VERSION 5.7 ;
BUSBITCHARS "[]" ;
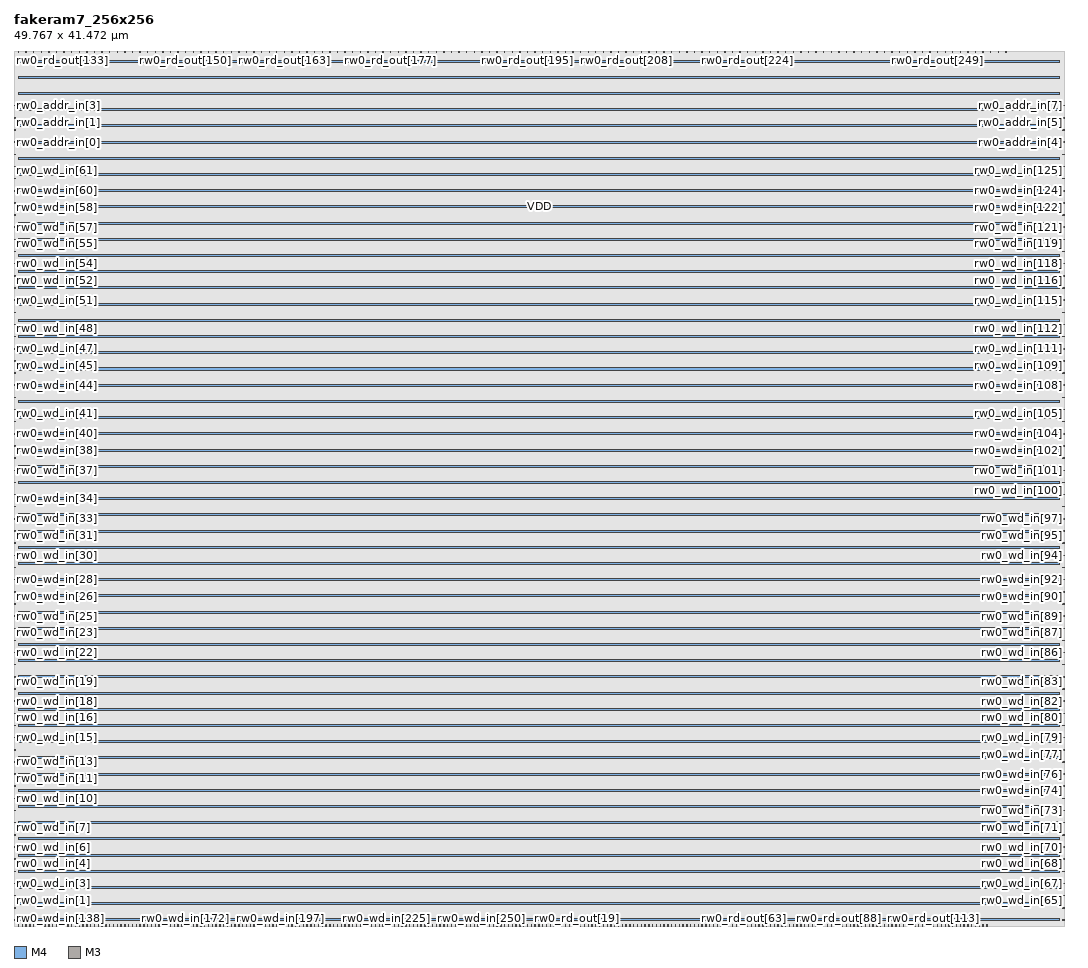
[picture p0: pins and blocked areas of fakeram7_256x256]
MACRO fakeram7_256x256
  FOREIGN fakeram7_256x256 0 0 ;
  SYMMETRY X Y R90 ;
  SIZE 49.767 BY 41.472 ;
  CLASS BLOCK ;
  PIN rw0_wd_in[0]
    DIRECTION INPUT ;
    USE SIGNAL ;
    SHAPE ABUTMENT ;
    PORT
      LAYER M4 ;
      RECT 0.000 0.276 0.072 0.300 ;
    END
  END rw0_wd_in[0]
  PIN rw0_wd_in[1]
    DIRECTION INPUT ;
    USE SIGNAL ;
    SHAPE ABUTMENT ;
    PORT
      LAYER M4 ;
      RECT 0.000 0.852 0.072 0.876 ;
    END
  END rw0_wd_in[1]
  PIN rw0_wd_in[2]
    DIRECTION INPUT ;
    USE SIGNAL ;
    SHAPE ABUTMENT ;
    PORT
      LAYER M4 ;
      RECT 0.000 1.428 0.072 1.452 ;
    END
  END rw0_wd_in[2]
  PIN rw0_wd_in[3]
    DIRECTION INPUT ;
    USE SIGNAL ;
    SHAPE ABUTMENT ;
    PORT
      LAYER M4 ;
      RECT 0.000 2.004 0.072 2.028 ;
    END
  END rw0_wd_in[3]
  PIN rw0_wd_in[4]
    DIRECTION INPUT ;
    USE SIGNAL ;
    SHAPE ABUTMENT ;
    PORT
      LAYER M4 ;
      RECT 0.000 2.580 0.072 2.604 ;
    END
  END rw0_wd_in[4]
  PIN rw0_wd_in[5]
    DIRECTION INPUT ;
    USE SIGNAL ;
    SHAPE ABUTMENT ;
    PORT
      LAYER M4 ;
      RECT 0.000 3.156 0.072 3.180 ;
    END
  END rw0_wd_in[5]
  PIN rw0_wd_in[6]
    DIRECTION INPUT ;
    USE SIGNAL ;
    SHAPE ABUTMENT ;
    PORT
      LAYER M4 ;
      RECT 0.000 3.732 0.072 3.756 ;
    END
  END rw0_wd_in[6]
  PIN rw0_wd_in[7]
    DIRECTION INPUT ;
    USE SIGNAL ;
    SHAPE ABUTMENT ;
    PORT
      LAYER M4 ;
      RECT 0.000 4.308 0.072 4.332 ;
    END
  END rw0_wd_in[7]
  PIN rw0_wd_in[8]
    DIRECTION INPUT ;
    USE SIGNAL ;
    SHAPE ABUTMENT ;
    PORT
      LAYER M4 ;
      RECT 0.000 4.884 0.072 4.908 ;
    END
  END rw0_wd_in[8]
  PIN rw0_wd_in[9]
    DIRECTION INPUT ;
    USE SIGNAL ;
    SHAPE ABUTMENT ;
    PORT
      LAYER M4 ;
      RECT 0.000 5.460 0.072 5.484 ;
    END
  END rw0_wd_in[9]
  PIN rw0_wd_in[10]
    DIRECTION INPUT ;
    USE SIGNAL ;
    SHAPE ABUTMENT ;
    PORT
      LAYER M4 ;
      RECT 0.000 6.036 0.072 6.060 ;
    END
  END rw0_wd_in[10]
  PIN rw0_wd_in[11]
    DIRECTION INPUT ;
    USE SIGNAL ;
    SHAPE ABUTMENT ;
    PORT
      LAYER M4 ;
      RECT 0.000 6.612 0.072 6.636 ;
    END
  END rw0_wd_in[11]
  PIN rw0_wd_in[12]
    DIRECTION INPUT ;
    USE SIGNAL ;
    SHAPE ABUTMENT ;
    PORT
      LAYER M4 ;
      RECT 0.000 7.188 0.072 7.212 ;
    END
  END rw0_wd_in[12]
  PIN rw0_wd_in[13]
    DIRECTION INPUT ;
    USE SIGNAL ;
    SHAPE ABUTMENT ;
    PORT
      LAYER M4 ;
      RECT 0.000 7.764 0.072 7.788 ;
    END
  END rw0_wd_in[13]
  PIN rw0_wd_in[14]
    DIRECTION INPUT ;
    USE SIGNAL ;
    SHAPE ABUTMENT ;
    PORT
      LAYER M4 ;
      RECT 0.000 8.340 0.072 8.364 ;
    END
  END rw0_wd_in[14]
  PIN rw0_wd_in[15]
    DIRECTION INPUT ;
    USE SIGNAL ;
    SHAPE ABUTMENT ;
    PORT
      LAYER M4 ;
      RECT 0.000 8.916 0.072 8.940 ;
    END
  END rw0_wd_in[15]
  PIN rw0_wd_in[16]
    DIRECTION INPUT ;
    USE SIGNAL ;
    SHAPE ABUTMENT ;
    PORT
      LAYER M4 ;
      RECT 0.000 9.492 0.072 9.516 ;
    END
  END rw0_wd_in[16]
  PIN rw0_wd_in[17]
    DIRECTION INPUT ;
    USE SIGNAL ;
    SHAPE ABUTMENT ;
    PORT
      LAYER M4 ;
      RECT 0.000 10.068 0.072 10.092 ;
    END
  END rw0_wd_in[17]
  PIN rw0_wd_in[18]
    DIRECTION INPUT ;
    USE SIGNAL ;
    SHAPE ABUTMENT ;
    PORT
      LAYER M4 ;
      RECT 0.000 10.644 0.072 10.668 ;
    END
  END rw0_wd_in[18]
  PIN rw0_wd_in[19]
    DIRECTION INPUT ;
    USE SIGNAL ;
    SHAPE ABUTMENT ;
    PORT
      LAYER M4 ;
      RECT 0.000 11.220 0.072 11.244 ;
    END
  END rw0_wd_in[19]
  PIN rw0_wd_in[20]
    DIRECTION INPUT ;
    USE SIGNAL ;
    SHAPE ABUTMENT ;
    PORT
      LAYER M4 ;
      RECT 0.000 11.796 0.072 11.820 ;
    END
  END rw0_wd_in[20]
  PIN rw0_wd_in[21]
    DIRECTION INPUT ;
    USE SIGNAL ;
    SHAPE ABUTMENT ;
    PORT
      LAYER M4 ;
      RECT 0.000 12.372 0.072 12.396 ;
    END
  END rw0_wd_in[21]
  PIN rw0_wd_in[22]
    DIRECTION INPUT ;
    USE SIGNAL ;
    SHAPE ABUTMENT ;
    PORT
      LAYER M4 ;
      RECT 0.000 12.948 0.072 12.972 ;
    END
  END rw0_wd_in[22]
  PIN rw0_wd_in[23]
    DIRECTION INPUT ;
    USE SIGNAL ;
    SHAPE ABUTMENT ;
    PORT
      LAYER M4 ;
      RECT 0.000 13.524 0.072 13.548 ;
    END
  END rw0_wd_in[23]
  PIN rw0_wd_in[24]
    DIRECTION INPUT ;
    USE SIGNAL ;
    SHAPE ABUTMENT ;
    PORT
      LAYER M4 ;
      RECT 0.000 14.100 0.072 14.124 ;
    END
  END rw0_wd_in[24]
  PIN rw0_wd_in[25]
    DIRECTION INPUT ;
    USE SIGNAL ;
    SHAPE ABUTMENT ;
    PORT
      LAYER M4 ;
      RECT 0.000 14.676 0.072 14.700 ;
    END
  END rw0_wd_in[25]
  PIN rw0_wd_in[26]
    DIRECTION INPUT ;
    USE SIGNAL ;
    SHAPE ABUTMENT ;
    PORT
      LAYER M4 ;
      RECT 0.000 15.252 0.072 15.276 ;
    END
  END rw0_wd_in[26]
  PIN rw0_wd_in[27]
    DIRECTION INPUT ;
    USE SIGNAL ;
    SHAPE ABUTMENT ;
    PORT
      LAYER M4 ;
      RECT 0.000 15.828 0.072 15.852 ;
    END
  END rw0_wd_in[27]
  PIN rw0_wd_in[28]
    DIRECTION INPUT ;
    USE SIGNAL ;
    SHAPE ABUTMENT ;
    PORT
      LAYER M4 ;
      RECT 0.000 16.404 0.072 16.428 ;
    END
  END rw0_wd_in[28]
  PIN rw0_wd_in[29]
    DIRECTION INPUT ;
    USE SIGNAL ;
    SHAPE ABUTMENT ;
    PORT
      LAYER M4 ;
      RECT 0.000 16.980 0.072 17.004 ;
    END
  END rw0_wd_in[29]
  PIN rw0_wd_in[30]
    DIRECTION INPUT ;
    USE SIGNAL ;
    SHAPE ABUTMENT ;
    PORT
      LAYER M4 ;
      RECT 0.000 17.556 0.072 17.580 ;
    END
  END rw0_wd_in[30]
  PIN rw0_wd_in[31]
    DIRECTION INPUT ;
    USE SIGNAL ;
    SHAPE ABUTMENT ;
    PORT
      LAYER M4 ;
      RECT 0.000 18.132 0.072 18.156 ;
    END
  END rw0_wd_in[31]
  PIN rw0_wd_in[32]
    DIRECTION INPUT ;
    USE SIGNAL ;
    SHAPE ABUTMENT ;
    PORT
      LAYER M4 ;
      RECT 0.000 18.708 0.072 18.732 ;
    END
  END rw0_wd_in[32]
  PIN rw0_wd_in[33]
    DIRECTION INPUT ;
    USE SIGNAL ;
    SHAPE ABUTMENT ;
    PORT
      LAYER M4 ;
      RECT 0.000 19.284 0.072 19.308 ;
    END
  END rw0_wd_in[33]
  PIN rw0_wd_in[34]
    DIRECTION INPUT ;
    USE SIGNAL ;
    SHAPE ABUTMENT ;
    PORT
      LAYER M4 ;
      RECT 0.000 19.860 0.072 19.884 ;
    END
  END rw0_wd_in[34]
  PIN rw0_wd_in[35]
    DIRECTION INPUT ;
    USE SIGNAL ;
    SHAPE ABUTMENT ;
    PORT
      LAYER M4 ;
      RECT 0.000 20.436 0.072 20.460 ;
    END
  END rw0_wd_in[35]
  PIN rw0_wd_in[36]
    DIRECTION INPUT ;
    USE SIGNAL ;
    SHAPE ABUTMENT ;
    PORT
      LAYER M4 ;
      RECT 0.000 21.012 0.072 21.036 ;
    END
  END rw0_wd_in[36]
  PIN rw0_wd_in[37]
    DIRECTION INPUT ;
    USE SIGNAL ;
    SHAPE ABUTMENT ;
    PORT
      LAYER M4 ;
      RECT 0.000 21.588 0.072 21.612 ;
    END
  END rw0_wd_in[37]
  PIN rw0_wd_in[38]
    DIRECTION INPUT ;
    USE SIGNAL ;
    SHAPE ABUTMENT ;
    PORT
      LAYER M4 ;
      RECT 0.000 22.164 0.072 22.188 ;
    END
  END rw0_wd_in[38]
  PIN rw0_wd_in[39]
    DIRECTION INPUT ;
    USE SIGNAL ;
    SHAPE ABUTMENT ;
    PORT
      LAYER M4 ;
      RECT 0.000 22.740 0.072 22.764 ;
    END
  END rw0_wd_in[39]
  PIN rw0_wd_in[40]
    DIRECTION INPUT ;
    USE SIGNAL ;
    SHAPE ABUTMENT ;
    PORT
      LAYER M4 ;
      RECT 0.000 23.316 0.072 23.340 ;
    END
  END rw0_wd_in[40]
  PIN rw0_wd_in[41]
    DIRECTION INPUT ;
    USE SIGNAL ;
    SHAPE ABUTMENT ;
    PORT
      LAYER M4 ;
      RECT 0.000 23.892 0.072 23.916 ;
    END
  END rw0_wd_in[41]
  PIN rw0_wd_in[42]
    DIRECTION INPUT ;
    USE SIGNAL ;
    SHAPE ABUTMENT ;
    PORT
      LAYER M4 ;
      RECT 0.000 24.468 0.072 24.492 ;
    END
  END rw0_wd_in[42]
  PIN rw0_wd_in[43]
    DIRECTION INPUT ;
    USE SIGNAL ;
    SHAPE ABUTMENT ;
    PORT
      LAYER M4 ;
      RECT 0.000 25.044 0.072 25.068 ;
    END
  END rw0_wd_in[43]
  PIN rw0_wd_in[44]
    DIRECTION INPUT ;
    USE SIGNAL ;
    SHAPE ABUTMENT ;
    PORT
      LAYER M4 ;
      RECT 0.000 25.620 0.072 25.644 ;
    END
  END rw0_wd_in[44]
  PIN rw0_wd_in[45]
    DIRECTION INPUT ;
    USE SIGNAL ;
    SHAPE ABUTMENT ;
    PORT
      LAYER M4 ;
      RECT 0.000 26.196 0.072 26.220 ;
    END
  END rw0_wd_in[45]
  PIN rw0_wd_in[46]
    DIRECTION INPUT ;
    USE SIGNAL ;
    SHAPE ABUTMENT ;
    PORT
      LAYER M4 ;
      RECT 0.000 26.772 0.072 26.796 ;
    END
  END rw0_wd_in[46]
  PIN rw0_wd_in[47]
    DIRECTION INPUT ;
    USE SIGNAL ;
    SHAPE ABUTMENT ;
    PORT
      LAYER M4 ;
      RECT 0.000 27.348 0.072 27.372 ;
    END
  END rw0_wd_in[47]
  PIN rw0_wd_in[48]
    DIRECTION INPUT ;
    USE SIGNAL ;
    SHAPE ABUTMENT ;
    PORT
      LAYER M4 ;
      RECT 0.000 27.924 0.072 27.948 ;
    END
  END rw0_wd_in[48]
  PIN rw0_wd_in[49]
    DIRECTION INPUT ;
    USE SIGNAL ;
    SHAPE ABUTMENT ;
    PORT
      LAYER M4 ;
      RECT 0.000 28.500 0.072 28.524 ;
    END
  END rw0_wd_in[49]
  PIN rw0_wd_in[50]
    DIRECTION INPUT ;
    USE SIGNAL ;
    SHAPE ABUTMENT ;
    PORT
      LAYER M4 ;
      RECT 0.000 29.076 0.072 29.100 ;
    END
  END rw0_wd_in[50]
  PIN rw0_wd_in[51]
    DIRECTION INPUT ;
    USE SIGNAL ;
    SHAPE ABUTMENT ;
    PORT
      LAYER M4 ;
      RECT 0.000 29.652 0.072 29.676 ;
    END
  END rw0_wd_in[51]
  PIN rw0_wd_in[52]
    DIRECTION INPUT ;
    USE SIGNAL ;
    SHAPE ABUTMENT ;
    PORT
      LAYER M4 ;
      RECT 0.000 30.228 0.072 30.252 ;
    END
  END rw0_wd_in[52]
  PIN rw0_wd_in[53]
    DIRECTION INPUT ;
    USE SIGNAL ;
    SHAPE ABUTMENT ;
    PORT
      LAYER M4 ;
      RECT 0.000 30.804 0.072 30.828 ;
    END
  END rw0_wd_in[53]
  PIN rw0_wd_in[54]
    DIRECTION INPUT ;
    USE SIGNAL ;
    SHAPE ABUTMENT ;
    PORT
      LAYER M4 ;
      RECT 0.000 31.380 0.072 31.404 ;
    END
  END rw0_wd_in[54]
  PIN rw0_wd_in[55]
    DIRECTION INPUT ;
    USE SIGNAL ;
    SHAPE ABUTMENT ;
    PORT
      LAYER M4 ;
      RECT 0.000 31.956 0.072 31.980 ;
    END
  END rw0_wd_in[55]
  PIN rw0_wd_in[56]
    DIRECTION INPUT ;
    USE SIGNAL ;
    SHAPE ABUTMENT ;
    PORT
      LAYER M4 ;
      RECT 0.000 32.532 0.072 32.556 ;
    END
  END rw0_wd_in[56]
  PIN rw0_wd_in[57]
    DIRECTION INPUT ;
    USE SIGNAL ;
    SHAPE ABUTMENT ;
    PORT
      LAYER M4 ;
      RECT 0.000 33.108 0.072 33.132 ;
    END
  END rw0_wd_in[57]
  PIN rw0_wd_in[58]
    DIRECTION INPUT ;
    USE SIGNAL ;
    SHAPE ABUTMENT ;
    PORT
      LAYER M4 ;
      RECT 0.000 33.684 0.072 33.708 ;
    END
  END rw0_wd_in[58]
  PIN rw0_wd_in[59]
    DIRECTION INPUT ;
    USE SIGNAL ;
    SHAPE ABUTMENT ;
    PORT
      LAYER M4 ;
      RECT 0.000 34.260 0.072 34.284 ;
    END
  END rw0_wd_in[59]
  PIN rw0_wd_in[60]
    DIRECTION INPUT ;
    USE SIGNAL ;
    SHAPE ABUTMENT ;
    PORT
      LAYER M4 ;
      RECT 0.000 34.836 0.072 34.860 ;
    END
  END rw0_wd_in[60]
  PIN rw0_wd_in[61]
    DIRECTION INPUT ;
    USE SIGNAL ;
    SHAPE ABUTMENT ;
    PORT
      LAYER M4 ;
      RECT 0.000 35.412 0.072 35.436 ;
    END
  END rw0_wd_in[61]
  PIN rw0_wd_in[62]
    DIRECTION INPUT ;
    USE SIGNAL ;
    SHAPE ABUTMENT ;
    PORT
      LAYER M4 ;
      RECT 0.000 35.988 0.072 36.012 ;
    END
  END rw0_wd_in[62]
  PIN rw0_wd_in[63]
    DIRECTION INPUT ;
    USE SIGNAL ;
    SHAPE ABUTMENT ;
    PORT
      LAYER M4 ;
      RECT 0.000 36.564 0.072 36.588 ;
    END
  END rw0_wd_in[63]
  PIN rw0_wd_in[64]
    DIRECTION INPUT ;
    USE SIGNAL ;
    SHAPE ABUTMENT ;
    PORT
      LAYER M4 ;
      RECT 49.695 0.276 49.767 0.300 ;
    END
  END rw0_wd_in[64]
  PIN rw0_wd_in[65]
    DIRECTION INPUT ;
    USE SIGNAL ;
    SHAPE ABUTMENT ;
    PORT
      LAYER M4 ;
      RECT 49.695 0.852 49.767 0.876 ;
    END
  END rw0_wd_in[65]
  PIN rw0_wd_in[66]
    DIRECTION INPUT ;
    USE SIGNAL ;
    SHAPE ABUTMENT ;
    PORT
      LAYER M4 ;
      RECT 49.695 1.428 49.767 1.452 ;
    END
  END rw0_wd_in[66]
  PIN rw0_wd_in[67]
    DIRECTION INPUT ;
    USE SIGNAL ;
    SHAPE ABUTMENT ;
    PORT
      LAYER M4 ;
      RECT 49.695 2.004 49.767 2.028 ;
    END
  END rw0_wd_in[67]
  PIN rw0_wd_in[68]
    DIRECTION INPUT ;
    USE SIGNAL ;
    SHAPE ABUTMENT ;
    PORT
      LAYER M4 ;
      RECT 49.695 2.580 49.767 2.604 ;
    END
  END rw0_wd_in[68]
  PIN rw0_wd_in[69]
    DIRECTION INPUT ;
    USE SIGNAL ;
    SHAPE ABUTMENT ;
    PORT
      LAYER M4 ;
      RECT 49.695 3.156 49.767 3.180 ;
    END
  END rw0_wd_in[69]
  PIN rw0_wd_in[70]
    DIRECTION INPUT ;
    USE SIGNAL ;
    SHAPE ABUTMENT ;
    PORT
      LAYER M4 ;
      RECT 49.695 3.732 49.767 3.756 ;
    END
  END rw0_wd_in[70]
  PIN rw0_wd_in[71]
    DIRECTION INPUT ;
    USE SIGNAL ;
    SHAPE ABUTMENT ;
    PORT
      LAYER M4 ;
      RECT 49.695 4.308 49.767 4.332 ;
    END
  END rw0_wd_in[71]
  PIN rw0_wd_in[72]
    DIRECTION INPUT ;
    USE SIGNAL ;
    SHAPE ABUTMENT ;
    PORT
      LAYER M4 ;
      RECT 49.695 4.884 49.767 4.908 ;
    END
  END rw0_wd_in[72]
  PIN rw0_wd_in[73]
    DIRECTION INPUT ;
    USE SIGNAL ;
    SHAPE ABUTMENT ;
    PORT
      LAYER M4 ;
      RECT 49.695 5.460 49.767 5.484 ;
    END
  END rw0_wd_in[73]
  PIN rw0_wd_in[74]
    DIRECTION INPUT ;
    USE SIGNAL ;
    SHAPE ABUTMENT ;
    PORT
      LAYER M4 ;
      RECT 49.695 6.036 49.767 6.060 ;
    END
  END rw0_wd_in[74]
  PIN rw0_wd_in[75]
    DIRECTION INPUT ;
    USE SIGNAL ;
    SHAPE ABUTMENT ;
    PORT
      LAYER M4 ;
      RECT 49.695 6.612 49.767 6.636 ;
    END
  END rw0_wd_in[75]
  PIN rw0_wd_in[76]
    DIRECTION INPUT ;
    USE SIGNAL ;
    SHAPE ABUTMENT ;
    PORT
      LAYER M4 ;
      RECT 49.695 7.188 49.767 7.212 ;
    END
  END rw0_wd_in[76]
  PIN rw0_wd_in[77]
    DIRECTION INPUT ;
    USE SIGNAL ;
    SHAPE ABUTMENT ;
    PORT
      LAYER M4 ;
      RECT 49.695 7.764 49.767 7.788 ;
    END
  END rw0_wd_in[77]
  PIN rw0_wd_in[78]
    DIRECTION INPUT ;
    USE SIGNAL ;
    SHAPE ABUTMENT ;
    PORT
      LAYER M4 ;
      RECT 49.695 8.340 49.767 8.364 ;
    END
  END rw0_wd_in[78]
  PIN rw0_wd_in[79]
    DIRECTION INPUT ;
    USE SIGNAL ;
    SHAPE ABUTMENT ;
    PORT
      LAYER M4 ;
      RECT 49.695 8.916 49.767 8.940 ;
    END
  END rw0_wd_in[79]
  PIN rw0_wd_in[80]
    DIRECTION INPUT ;
    USE SIGNAL ;
    SHAPE ABUTMENT ;
    PORT
      LAYER M4 ;
      RECT 49.695 9.492 49.767 9.516 ;
    END
  END rw0_wd_in[80]
  PIN rw0_wd_in[81]
    DIRECTION INPUT ;
    USE SIGNAL ;
    SHAPE ABUTMENT ;
    PORT
      LAYER M4 ;
      RECT 49.695 10.068 49.767 10.092 ;
    END
  END rw0_wd_in[81]
  PIN rw0_wd_in[82]
    DIRECTION INPUT ;
    USE SIGNAL ;
    SHAPE ABUTMENT ;
    PORT
      LAYER M4 ;
      RECT 49.695 10.644 49.767 10.668 ;
    END
  END rw0_wd_in[82]
  PIN rw0_wd_in[83]
    DIRECTION INPUT ;
    USE SIGNAL ;
    SHAPE ABUTMENT ;
    PORT
      LAYER M4 ;
      RECT 49.695 11.220 49.767 11.244 ;
    END
  END rw0_wd_in[83]
  PIN rw0_wd_in[84]
    DIRECTION INPUT ;
    USE SIGNAL ;
    SHAPE ABUTMENT ;
    PORT
      LAYER M4 ;
      RECT 49.695 11.796 49.767 11.820 ;
    END
  END rw0_wd_in[84]
  PIN rw0_wd_in[85]
    DIRECTION INPUT ;
    USE SIGNAL ;
    SHAPE ABUTMENT ;
    PORT
      LAYER M4 ;
      RECT 49.695 12.372 49.767 12.396 ;
    END
  END rw0_wd_in[85]
  PIN rw0_wd_in[86]
    DIRECTION INPUT ;
    USE SIGNAL ;
    SHAPE ABUTMENT ;
    PORT
      LAYER M4 ;
      RECT 49.695 12.948 49.767 12.972 ;
    END
  END rw0_wd_in[86]
  PIN rw0_wd_in[87]
    DIRECTION INPUT ;
    USE SIGNAL ;
    SHAPE ABUTMENT ;
    PORT
      LAYER M4 ;
      RECT 49.695 13.524 49.767 13.548 ;
    END
  END rw0_wd_in[87]
  PIN rw0_wd_in[88]
    DIRECTION INPUT ;
    USE SIGNAL ;
    SHAPE ABUTMENT ;
    PORT
      LAYER M4 ;
      RECT 49.695 14.100 49.767 14.124 ;
    END
  END rw0_wd_in[88]
  PIN rw0_wd_in[89]
    DIRECTION INPUT ;
    USE SIGNAL ;
    SHAPE ABUTMENT ;
    PORT
      LAYER M4 ;
      RECT 49.695 14.676 49.767 14.700 ;
    END
  END rw0_wd_in[89]
  PIN rw0_wd_in[90]
    DIRECTION INPUT ;
    USE SIGNAL ;
    SHAPE ABUTMENT ;
    PORT
      LAYER M4 ;
      RECT 49.695 15.252 49.767 15.276 ;
    END
  END rw0_wd_in[90]
  PIN rw0_wd_in[91]
    DIRECTION INPUT ;
    USE SIGNAL ;
    SHAPE ABUTMENT ;
    PORT
      LAYER M4 ;
      RECT 49.695 15.828 49.767 15.852 ;
    END
  END rw0_wd_in[91]
  PIN rw0_wd_in[92]
    DIRECTION INPUT ;
    USE SIGNAL ;
    SHAPE ABUTMENT ;
    PORT
      LAYER M4 ;
      RECT 49.695 16.404 49.767 16.428 ;
    END
  END rw0_wd_in[92]
  PIN rw0_wd_in[93]
    DIRECTION INPUT ;
    USE SIGNAL ;
    SHAPE ABUTMENT ;
    PORT
      LAYER M4 ;
      RECT 49.695 16.980 49.767 17.004 ;
    END
  END rw0_wd_in[93]
  PIN rw0_wd_in[94]
    DIRECTION INPUT ;
    USE SIGNAL ;
    SHAPE ABUTMENT ;
    PORT
      LAYER M4 ;
      RECT 49.695 17.556 49.767 17.580 ;
    END
  END rw0_wd_in[94]
  PIN rw0_wd_in[95]
    DIRECTION INPUT ;
    USE SIGNAL ;
    SHAPE ABUTMENT ;
    PORT
      LAYER M4 ;
      RECT 49.695 18.132 49.767 18.156 ;
    END
  END rw0_wd_in[95]
  PIN rw0_wd_in[96]
    DIRECTION INPUT ;
    USE SIGNAL ;
    SHAPE ABUTMENT ;
    PORT
      LAYER M4 ;
      RECT 49.695 18.708 49.767 18.732 ;
    END
  END rw0_wd_in[96]
  PIN rw0_wd_in[97]
    DIRECTION INPUT ;
    USE SIGNAL ;
    SHAPE ABUTMENT ;
    PORT
      LAYER M4 ;
      RECT 49.695 19.284 49.767 19.308 ;
    END
  END rw0_wd_in[97]
  PIN rw0_wd_in[98]
    DIRECTION INPUT ;
    USE SIGNAL ;
    SHAPE ABUTMENT ;
    PORT
      LAYER M4 ;
      RECT 49.695 19.860 49.767 19.884 ;
    END
  END rw0_wd_in[98]
  PIN rw0_wd_in[99]
    DIRECTION INPUT ;
    USE SIGNAL ;
    SHAPE ABUTMENT ;
    PORT
      LAYER M4 ;
      RECT 49.695 20.436 49.767 20.460 ;
    END
  END rw0_wd_in[99]
  PIN rw0_wd_in[100]
    DIRECTION INPUT ;
    USE SIGNAL ;
    SHAPE ABUTMENT ;
    PORT
      LAYER M4 ;
      RECT 49.695 21.012 49.767 21.036 ;
    END
  END rw0_wd_in[100]
  PIN rw0_wd_in[101]
    DIRECTION INPUT ;
    USE SIGNAL ;
    SHAPE ABUTMENT ;
    PORT
      LAYER M4 ;
      RECT 49.695 21.588 49.767 21.612 ;
    END
  END rw0_wd_in[101]
  PIN rw0_wd_in[102]
    DIRECTION INPUT ;
    USE SIGNAL ;
    SHAPE ABUTMENT ;
    PORT
      LAYER M4 ;
      RECT 49.695 22.164 49.767 22.188 ;
    END
  END rw0_wd_in[102]
  PIN rw0_wd_in[103]
    DIRECTION INPUT ;
    USE SIGNAL ;
    SHAPE ABUTMENT ;
    PORT
      LAYER M4 ;
      RECT 49.695 22.740 49.767 22.764 ;
    END
  END rw0_wd_in[103]
  PIN rw0_wd_in[104]
    DIRECTION INPUT ;
    USE SIGNAL ;
    SHAPE ABUTMENT ;
    PORT
      LAYER M4 ;
      RECT 49.695 23.316 49.767 23.340 ;
    END
  END rw0_wd_in[104]
  PIN rw0_wd_in[105]
    DIRECTION INPUT ;
    USE SIGNAL ;
    SHAPE ABUTMENT ;
    PORT
      LAYER M4 ;
      RECT 49.695 23.892 49.767 23.916 ;
    END
  END rw0_wd_in[105]
  PIN rw0_wd_in[106]
    DIRECTION INPUT ;
    USE SIGNAL ;
    SHAPE ABUTMENT ;
    PORT
      LAYER M4 ;
      RECT 49.695 24.468 49.767 24.492 ;
    END
  END rw0_wd_in[106]
  PIN rw0_wd_in[107]
    DIRECTION INPUT ;
    USE SIGNAL ;
    SHAPE ABUTMENT ;
    PORT
      LAYER M4 ;
      RECT 49.695 25.044 49.767 25.068 ;
    END
  END rw0_wd_in[107]
  PIN rw0_wd_in[108]
    DIRECTION INPUT ;
    USE SIGNAL ;
    SHAPE ABUTMENT ;
    PORT
      LAYER M4 ;
      RECT 49.695 25.620 49.767 25.644 ;
    END
  END rw0_wd_in[108]
  PIN rw0_wd_in[109]
    DIRECTION INPUT ;
    USE SIGNAL ;
    SHAPE ABUTMENT ;
    PORT
      LAYER M4 ;
      RECT 49.695 26.196 49.767 26.220 ;
    END
  END rw0_wd_in[109]
  PIN rw0_wd_in[110]
    DIRECTION INPUT ;
    USE SIGNAL ;
    SHAPE ABUTMENT ;
    PORT
      LAYER M4 ;
      RECT 49.695 26.772 49.767 26.796 ;
    END
  END rw0_wd_in[110]
  PIN rw0_wd_in[111]
    DIRECTION INPUT ;
    USE SIGNAL ;
    SHAPE ABUTMENT ;
    PORT
      LAYER M4 ;
      RECT 49.695 27.348 49.767 27.372 ;
    END
  END rw0_wd_in[111]
  PIN rw0_wd_in[112]
    DIRECTION INPUT ;
    USE SIGNAL ;
    SHAPE ABUTMENT ;
    PORT
      LAYER M4 ;
      RECT 49.695 27.924 49.767 27.948 ;
    END
  END rw0_wd_in[112]
  PIN rw0_wd_in[113]
    DIRECTION INPUT ;
    USE SIGNAL ;
    SHAPE ABUTMENT ;
    PORT
      LAYER M4 ;
      RECT 49.695 28.500 49.767 28.524 ;
    END
  END rw0_wd_in[113]
  PIN rw0_wd_in[114]
    DIRECTION INPUT ;
    USE SIGNAL ;
    SHAPE ABUTMENT ;
    PORT
      LAYER M4 ;
      RECT 49.695 29.076 49.767 29.100 ;
    END
  END rw0_wd_in[114]
  PIN rw0_wd_in[115]
    DIRECTION INPUT ;
    USE SIGNAL ;
    SHAPE ABUTMENT ;
    PORT
      LAYER M4 ;
      RECT 49.695 29.652 49.767 29.676 ;
    END
  END rw0_wd_in[115]
  PIN rw0_wd_in[116]
    DIRECTION INPUT ;
    USE SIGNAL ;
    SHAPE ABUTMENT ;
    PORT
      LAYER M4 ;
      RECT 49.695 30.228 49.767 30.252 ;
    END
  END rw0_wd_in[116]
  PIN rw0_wd_in[117]
    DIRECTION INPUT ;
    USE SIGNAL ;
    SHAPE ABUTMENT ;
    PORT
      LAYER M4 ;
      RECT 49.695 30.804 49.767 30.828 ;
    END
  END rw0_wd_in[117]
  PIN rw0_wd_in[118]
    DIRECTION INPUT ;
    USE SIGNAL ;
    SHAPE ABUTMENT ;
    PORT
      LAYER M4 ;
      RECT 49.695 31.380 49.767 31.404 ;
    END
  END rw0_wd_in[118]
  PIN rw0_wd_in[119]
    DIRECTION INPUT ;
    USE SIGNAL ;
    SHAPE ABUTMENT ;
    PORT
      LAYER M4 ;
      RECT 49.695 31.956 49.767 31.980 ;
    END
  END rw0_wd_in[119]
  PIN rw0_wd_in[120]
    DIRECTION INPUT ;
    USE SIGNAL ;
    SHAPE ABUTMENT ;
    PORT
      LAYER M4 ;
      RECT 49.695 32.532 49.767 32.556 ;
    END
  END rw0_wd_in[120]
  PIN rw0_wd_in[121]
    DIRECTION INPUT ;
    USE SIGNAL ;
    SHAPE ABUTMENT ;
    PORT
      LAYER M4 ;
      RECT 49.695 33.108 49.767 33.132 ;
    END
  END rw0_wd_in[121]
  PIN rw0_wd_in[122]
    DIRECTION INPUT ;
    USE SIGNAL ;
    SHAPE ABUTMENT ;
    PORT
      LAYER M4 ;
      RECT 49.695 33.684 49.767 33.708 ;
    END
  END rw0_wd_in[122]
  PIN rw0_wd_in[123]
    DIRECTION INPUT ;
    USE SIGNAL ;
    SHAPE ABUTMENT ;
    PORT
      LAYER M4 ;
      RECT 49.695 34.260 49.767 34.284 ;
    END
  END rw0_wd_in[123]
  PIN rw0_wd_in[124]
    DIRECTION INPUT ;
    USE SIGNAL ;
    SHAPE ABUTMENT ;
    PORT
      LAYER M4 ;
      RECT 49.695 34.836 49.767 34.860 ;
    END
  END rw0_wd_in[124]
  PIN rw0_wd_in[125]
    DIRECTION INPUT ;
    USE SIGNAL ;
    SHAPE ABUTMENT ;
    PORT
      LAYER M4 ;
      RECT 49.695 35.412 49.767 35.436 ;
    END
  END rw0_wd_in[125]
  PIN rw0_wd_in[126]
    DIRECTION INPUT ;
    USE SIGNAL ;
    SHAPE ABUTMENT ;
    PORT
      LAYER M4 ;
      RECT 49.695 35.988 49.767 36.012 ;
    END
  END rw0_wd_in[126]
  PIN rw0_wd_in[127]
    DIRECTION INPUT ;
    USE SIGNAL ;
    SHAPE ABUTMENT ;
    PORT
      LAYER M4 ;
      RECT 49.695 36.564 49.767 36.588 ;
    END
  END rw0_wd_in[127]
  PIN rw0_wd_in[128]
    DIRECTION OUTPUT ;
    USE SIGNAL ;
    SHAPE ABUTMENT ;
    PORT
      LAYER M3 ;
      RECT 0.207 0.000 0.225 0.054 ;
    END
  END rw0_wd_in[128]
  PIN rw0_wd_in[129]
    DIRECTION OUTPUT ;
    USE SIGNAL ;
    SHAPE ABUTMENT ;
    PORT
      LAYER M3 ;
      RECT 0.387 0.000 0.405 0.054 ;
    END
  END rw0_wd_in[129]
  PIN rw0_wd_in[130]
    DIRECTION OUTPUT ;
    USE SIGNAL ;
    SHAPE ABUTMENT ;
    PORT
      LAYER M3 ;
      RECT 0.567 0.000 0.585 0.054 ;
    END
  END rw0_wd_in[130]
  PIN rw0_wd_in[131]
    DIRECTION OUTPUT ;
    USE SIGNAL ;
    SHAPE ABUTMENT ;
    PORT
      LAYER M3 ;
      RECT 0.747 0.000 0.765 0.054 ;
    END
  END rw0_wd_in[131]
  PIN rw0_wd_in[132]
    DIRECTION OUTPUT ;
    USE SIGNAL ;
    SHAPE ABUTMENT ;
    PORT
      LAYER M3 ;
      RECT 0.927 0.000 0.945 0.054 ;
    END
  END rw0_wd_in[132]
  PIN rw0_wd_in[133]
    DIRECTION OUTPUT ;
    USE SIGNAL ;
    SHAPE ABUTMENT ;
    PORT
      LAYER M3 ;
      RECT 1.107 0.000 1.125 0.054 ;
    END
  END rw0_wd_in[133]
  PIN rw0_wd_in[134]
    DIRECTION OUTPUT ;
    USE SIGNAL ;
    SHAPE ABUTMENT ;
    PORT
      LAYER M3 ;
      RECT 1.287 0.000 1.305 0.054 ;
    END
  END rw0_wd_in[134]
  PIN rw0_wd_in[135]
    DIRECTION OUTPUT ;
    USE SIGNAL ;
    SHAPE ABUTMENT ;
    PORT
      LAYER M3 ;
      RECT 1.467 0.000 1.485 0.054 ;
    END
  END rw0_wd_in[135]
  PIN rw0_wd_in[136]
    DIRECTION OUTPUT ;
    USE SIGNAL ;
    SHAPE ABUTMENT ;
    PORT
      LAYER M3 ;
      RECT 1.647 0.000 1.665 0.054 ;
    END
  END rw0_wd_in[136]
  PIN rw0_wd_in[137]
    DIRECTION OUTPUT ;
    USE SIGNAL ;
    SHAPE ABUTMENT ;
    PORT
      LAYER M3 ;
      RECT 1.827 0.000 1.845 0.054 ;
    END
  END rw0_wd_in[137]
  PIN rw0_wd_in[138]
    DIRECTION OUTPUT ;
    USE SIGNAL ;
    SHAPE ABUTMENT ;
    PORT
      LAYER M3 ;
      RECT 2.007 0.000 2.025 0.054 ;
    END
  END rw0_wd_in[138]
  PIN rw0_wd_in[139]
    DIRECTION OUTPUT ;
    USE SIGNAL ;
    SHAPE ABUTMENT ;
    PORT
      LAYER M3 ;
      RECT 2.187 0.000 2.205 0.054 ;
    END
  END rw0_wd_in[139]
  PIN rw0_wd_in[140]
    DIRECTION OUTPUT ;
    USE SIGNAL ;
    SHAPE ABUTMENT ;
    PORT
      LAYER M3 ;
      RECT 2.367 0.000 2.385 0.054 ;
    END
  END rw0_wd_in[140]
  PIN rw0_wd_in[141]
    DIRECTION OUTPUT ;
    USE SIGNAL ;
    SHAPE ABUTMENT ;
    PORT
      LAYER M3 ;
      RECT 2.547 0.000 2.565 0.054 ;
    END
  END rw0_wd_in[141]
  PIN rw0_wd_in[142]
    DIRECTION OUTPUT ;
    USE SIGNAL ;
    SHAPE ABUTMENT ;
    PORT
      LAYER M3 ;
      RECT 2.727 0.000 2.745 0.054 ;
    END
  END rw0_wd_in[142]
  PIN rw0_wd_in[143]
    DIRECTION OUTPUT ;
    USE SIGNAL ;
    SHAPE ABUTMENT ;
    PORT
      LAYER M3 ;
      RECT 2.907 0.000 2.925 0.054 ;
    END
  END rw0_wd_in[143]
  PIN rw0_wd_in[144]
    DIRECTION OUTPUT ;
    USE SIGNAL ;
    SHAPE ABUTMENT ;
    PORT
      LAYER M3 ;
      RECT 3.087 0.000 3.105 0.054 ;
    END
  END rw0_wd_in[144]
  PIN rw0_wd_in[145]
    DIRECTION OUTPUT ;
    USE SIGNAL ;
    SHAPE ABUTMENT ;
    PORT
      LAYER M3 ;
      RECT 3.267 0.000 3.285 0.054 ;
    END
  END rw0_wd_in[145]
  PIN rw0_wd_in[146]
    DIRECTION OUTPUT ;
    USE SIGNAL ;
    SHAPE ABUTMENT ;
    PORT
      LAYER M3 ;
      RECT 3.447 0.000 3.465 0.054 ;
    END
  END rw0_wd_in[146]
  PIN rw0_wd_in[147]
    DIRECTION OUTPUT ;
    USE SIGNAL ;
    SHAPE ABUTMENT ;
    PORT
      LAYER M3 ;
      RECT 3.627 0.000 3.645 0.054 ;
    END
  END rw0_wd_in[147]
  PIN rw0_wd_in[148]
    DIRECTION OUTPUT ;
    USE SIGNAL ;
    SHAPE ABUTMENT ;
    PORT
      LAYER M3 ;
      RECT 3.807 0.000 3.825 0.054 ;
    END
  END rw0_wd_in[148]
  PIN rw0_wd_in[149]
    DIRECTION OUTPUT ;
    USE SIGNAL ;
    SHAPE ABUTMENT ;
    PORT
      LAYER M3 ;
      RECT 3.987 0.000 4.005 0.054 ;
    END
  END rw0_wd_in[149]
  PIN rw0_wd_in[150]
    DIRECTION OUTPUT ;
    USE SIGNAL ;
    SHAPE ABUTMENT ;
    PORT
      LAYER M3 ;
      RECT 4.167 0.000 4.185 0.054 ;
    END
  END rw0_wd_in[150]
  PIN rw0_wd_in[151]
    DIRECTION OUTPUT ;
    USE SIGNAL ;
    SHAPE ABUTMENT ;
    PORT
      LAYER M3 ;
      RECT 4.347 0.000 4.365 0.054 ;
    END
  END rw0_wd_in[151]
  PIN rw0_wd_in[152]
    DIRECTION OUTPUT ;
    USE SIGNAL ;
    SHAPE ABUTMENT ;
    PORT
      LAYER M3 ;
      RECT 4.527 0.000 4.545 0.054 ;
    END
  END rw0_wd_in[152]
  PIN rw0_wd_in[153]
    DIRECTION OUTPUT ;
    USE SIGNAL ;
    SHAPE ABUTMENT ;
    PORT
      LAYER M3 ;
      RECT 4.707 0.000 4.725 0.054 ;
    END
  END rw0_wd_in[153]
  PIN rw0_wd_in[154]
    DIRECTION OUTPUT ;
    USE SIGNAL ;
    SHAPE ABUTMENT ;
    PORT
      LAYER M3 ;
      RECT 4.887 0.000 4.905 0.054 ;
    END
  END rw0_wd_in[154]
  PIN rw0_wd_in[155]
    DIRECTION OUTPUT ;
    USE SIGNAL ;
    SHAPE ABUTMENT ;
    PORT
      LAYER M3 ;
      RECT 5.067 0.000 5.085 0.054 ;
    END
  END rw0_wd_in[155]
  PIN rw0_wd_in[156]
    DIRECTION OUTPUT ;
    USE SIGNAL ;
    SHAPE ABUTMENT ;
    PORT
      LAYER M3 ;
      RECT 5.247 0.000 5.265 0.054 ;
    END
  END rw0_wd_in[156]
  PIN rw0_wd_in[157]
    DIRECTION OUTPUT ;
    USE SIGNAL ;
    SHAPE ABUTMENT ;
    PORT
      LAYER M3 ;
      RECT 5.427 0.000 5.445 0.054 ;
    END
  END rw0_wd_in[157]
  PIN rw0_wd_in[158]
    DIRECTION OUTPUT ;
    USE SIGNAL ;
    SHAPE ABUTMENT ;
    PORT
      LAYER M3 ;
      RECT 5.607 0.000 5.625 0.054 ;
    END
  END rw0_wd_in[158]
  PIN rw0_wd_in[159]
    DIRECTION OUTPUT ;
    USE SIGNAL ;
    SHAPE ABUTMENT ;
    PORT
      LAYER M3 ;
      RECT 5.787 0.000 5.805 0.054 ;
    END
  END rw0_wd_in[159]
  PIN rw0_wd_in[160]
    DIRECTION OUTPUT ;
    USE SIGNAL ;
    SHAPE ABUTMENT ;
    PORT
      LAYER M3 ;
      RECT 5.967 0.000 5.985 0.054 ;
    END
  END rw0_wd_in[160]
  PIN rw0_wd_in[161]
    DIRECTION OUTPUT ;
    USE SIGNAL ;
    SHAPE ABUTMENT ;
    PORT
      LAYER M3 ;
      RECT 6.147 0.000 6.165 0.054 ;
    END
  END rw0_wd_in[161]
  PIN rw0_wd_in[162]
    DIRECTION OUTPUT ;
    USE SIGNAL ;
    SHAPE ABUTMENT ;
    PORT
      LAYER M3 ;
      RECT 6.327 0.000 6.345 0.054 ;
    END
  END rw0_wd_in[162]
  PIN rw0_wd_in[163]
    DIRECTION OUTPUT ;
    USE SIGNAL ;
    SHAPE ABUTMENT ;
    PORT
      LAYER M3 ;
      RECT 6.507 0.000 6.525 0.054 ;
    END
  END rw0_wd_in[163]
  PIN rw0_wd_in[164]
    DIRECTION OUTPUT ;
    USE SIGNAL ;
    SHAPE ABUTMENT ;
    PORT
      LAYER M3 ;
      RECT 6.687 0.000 6.705 0.054 ;
    END
  END rw0_wd_in[164]
  PIN rw0_wd_in[165]
    DIRECTION OUTPUT ;
    USE SIGNAL ;
    SHAPE ABUTMENT ;
    PORT
      LAYER M3 ;
      RECT 6.867 0.000 6.885 0.054 ;
    END
  END rw0_wd_in[165]
  PIN rw0_wd_in[166]
    DIRECTION OUTPUT ;
    USE SIGNAL ;
    SHAPE ABUTMENT ;
    PORT
      LAYER M3 ;
      RECT 7.047 0.000 7.065 0.054 ;
    END
  END rw0_wd_in[166]
  PIN rw0_wd_in[167]
    DIRECTION OUTPUT ;
    USE SIGNAL ;
    SHAPE ABUTMENT ;
    PORT
      LAYER M3 ;
      RECT 7.227 0.000 7.245 0.054 ;
    END
  END rw0_wd_in[167]
  PIN rw0_wd_in[168]
    DIRECTION OUTPUT ;
    USE SIGNAL ;
    SHAPE ABUTMENT ;
    PORT
      LAYER M3 ;
      RECT 7.407 0.000 7.425 0.054 ;
    END
  END rw0_wd_in[168]
  PIN rw0_wd_in[169]
    DIRECTION OUTPUT ;
    USE SIGNAL ;
    SHAPE ABUTMENT ;
    PORT
      LAYER M3 ;
      RECT 7.587 0.000 7.605 0.054 ;
    END
  END rw0_wd_in[169]
  PIN rw0_wd_in[170]
    DIRECTION OUTPUT ;
    USE SIGNAL ;
    SHAPE ABUTMENT ;
    PORT
      LAYER M3 ;
      RECT 7.767 0.000 7.785 0.054 ;
    END
  END rw0_wd_in[170]
  PIN rw0_wd_in[171]
    DIRECTION OUTPUT ;
    USE SIGNAL ;
    SHAPE ABUTMENT ;
    PORT
      LAYER M3 ;
      RECT 7.947 0.000 7.965 0.054 ;
    END
  END rw0_wd_in[171]
  PIN rw0_wd_in[172]
    DIRECTION OUTPUT ;
    USE SIGNAL ;
    SHAPE ABUTMENT ;
    PORT
      LAYER M3 ;
      RECT 8.127 0.000 8.145 0.054 ;
    END
  END rw0_wd_in[172]
  PIN rw0_wd_in[173]
    DIRECTION OUTPUT ;
    USE SIGNAL ;
    SHAPE ABUTMENT ;
    PORT
      LAYER M3 ;
      RECT 8.307 0.000 8.325 0.054 ;
    END
  END rw0_wd_in[173]
  PIN rw0_wd_in[174]
    DIRECTION OUTPUT ;
    USE SIGNAL ;
    SHAPE ABUTMENT ;
    PORT
      LAYER M3 ;
      RECT 8.487 0.000 8.505 0.054 ;
    END
  END rw0_wd_in[174]
  PIN rw0_wd_in[175]
    DIRECTION OUTPUT ;
    USE SIGNAL ;
    SHAPE ABUTMENT ;
    PORT
      LAYER M3 ;
      RECT 8.667 0.000 8.685 0.054 ;
    END
  END rw0_wd_in[175]
  PIN rw0_wd_in[176]
    DIRECTION OUTPUT ;
    USE SIGNAL ;
    SHAPE ABUTMENT ;
    PORT
      LAYER M3 ;
      RECT 8.847 0.000 8.865 0.054 ;
    END
  END rw0_wd_in[176]
  PIN rw0_wd_in[177]
    DIRECTION OUTPUT ;
    USE SIGNAL ;
    SHAPE ABUTMENT ;
    PORT
      LAYER M3 ;
      RECT 9.027 0.000 9.045 0.054 ;
    END
  END rw0_wd_in[177]
  PIN rw0_wd_in[178]
    DIRECTION OUTPUT ;
    USE SIGNAL ;
    SHAPE ABUTMENT ;
    PORT
      LAYER M3 ;
      RECT 9.207 0.000 9.225 0.054 ;
    END
  END rw0_wd_in[178]
  PIN rw0_wd_in[179]
    DIRECTION OUTPUT ;
    USE SIGNAL ;
    SHAPE ABUTMENT ;
    PORT
      LAYER M3 ;
      RECT 9.387 0.000 9.405 0.054 ;
    END
  END rw0_wd_in[179]
  PIN rw0_wd_in[180]
    DIRECTION OUTPUT ;
    USE SIGNAL ;
    SHAPE ABUTMENT ;
    PORT
      LAYER M3 ;
      RECT 9.567 0.000 9.585 0.054 ;
    END
  END rw0_wd_in[180]
  PIN rw0_wd_in[181]
    DIRECTION OUTPUT ;
    USE SIGNAL ;
    SHAPE ABUTMENT ;
    PORT
      LAYER M3 ;
      RECT 9.747 0.000 9.765 0.054 ;
    END
  END rw0_wd_in[181]
  PIN rw0_wd_in[182]
    DIRECTION OUTPUT ;
    USE SIGNAL ;
    SHAPE ABUTMENT ;
    PORT
      LAYER M3 ;
      RECT 9.927 0.000 9.945 0.054 ;
    END
  END rw0_wd_in[182]
  PIN rw0_wd_in[183]
    DIRECTION OUTPUT ;
    USE SIGNAL ;
    SHAPE ABUTMENT ;
    PORT
      LAYER M3 ;
      RECT 10.107 0.000 10.125 0.054 ;
    END
  END rw0_wd_in[183]
  PIN rw0_wd_in[184]
    DIRECTION OUTPUT ;
    USE SIGNAL ;
    SHAPE ABUTMENT ;
    PORT
      LAYER M3 ;
      RECT 10.287 0.000 10.305 0.054 ;
    END
  END rw0_wd_in[184]
  PIN rw0_wd_in[185]
    DIRECTION OUTPUT ;
    USE SIGNAL ;
    SHAPE ABUTMENT ;
    PORT
      LAYER M3 ;
      RECT 10.467 0.000 10.485 0.054 ;
    END
  END rw0_wd_in[185]
  PIN rw0_wd_in[186]
    DIRECTION OUTPUT ;
    USE SIGNAL ;
    SHAPE ABUTMENT ;
    PORT
      LAYER M3 ;
      RECT 10.647 0.000 10.665 0.054 ;
    END
  END rw0_wd_in[186]
  PIN rw0_wd_in[187]
    DIRECTION OUTPUT ;
    USE SIGNAL ;
    SHAPE ABUTMENT ;
    PORT
      LAYER M3 ;
      RECT 10.827 0.000 10.845 0.054 ;
    END
  END rw0_wd_in[187]
  PIN rw0_wd_in[188]
    DIRECTION OUTPUT ;
    USE SIGNAL ;
    SHAPE ABUTMENT ;
    PORT
      LAYER M3 ;
      RECT 11.007 0.000 11.025 0.054 ;
    END
  END rw0_wd_in[188]
  PIN rw0_wd_in[189]
    DIRECTION OUTPUT ;
    USE SIGNAL ;
    SHAPE ABUTMENT ;
    PORT
      LAYER M3 ;
      RECT 11.187 0.000 11.205 0.054 ;
    END
  END rw0_wd_in[189]
  PIN rw0_wd_in[190]
    DIRECTION OUTPUT ;
    USE SIGNAL ;
    SHAPE ABUTMENT ;
    PORT
      LAYER M3 ;
      RECT 11.367 0.000 11.385 0.054 ;
    END
  END rw0_wd_in[190]
  PIN rw0_wd_in[191]
    DIRECTION OUTPUT ;
    USE SIGNAL ;
    SHAPE ABUTMENT ;
    PORT
      LAYER M3 ;
      RECT 11.547 0.000 11.565 0.054 ;
    END
  END rw0_wd_in[191]
  PIN rw0_wd_in[192]
    DIRECTION OUTPUT ;
    USE SIGNAL ;
    SHAPE ABUTMENT ;
    PORT
      LAYER M3 ;
      RECT 11.727 0.000 11.745 0.054 ;
    END
  END rw0_wd_in[192]
  PIN rw0_wd_in[193]
    DIRECTION OUTPUT ;
    USE SIGNAL ;
    SHAPE ABUTMENT ;
    PORT
      LAYER M3 ;
      RECT 11.907 0.000 11.925 0.054 ;
    END
  END rw0_wd_in[193]
  PIN rw0_wd_in[194]
    DIRECTION OUTPUT ;
    USE SIGNAL ;
    SHAPE ABUTMENT ;
    PORT
      LAYER M3 ;
      RECT 12.087 0.000 12.105 0.054 ;
    END
  END rw0_wd_in[194]
  PIN rw0_wd_in[195]
    DIRECTION OUTPUT ;
    USE SIGNAL ;
    SHAPE ABUTMENT ;
    PORT
      LAYER M3 ;
      RECT 12.267 0.000 12.285 0.054 ;
    END
  END rw0_wd_in[195]
  PIN rw0_wd_in[196]
    DIRECTION OUTPUT ;
    USE SIGNAL ;
    SHAPE ABUTMENT ;
    PORT
      LAYER M3 ;
      RECT 12.447 0.000 12.465 0.054 ;
    END
  END rw0_wd_in[196]
  PIN rw0_wd_in[197]
    DIRECTION OUTPUT ;
    USE SIGNAL ;
    SHAPE ABUTMENT ;
    PORT
      LAYER M3 ;
      RECT 12.627 0.000 12.645 0.054 ;
    END
  END rw0_wd_in[197]
  PIN rw0_wd_in[198]
    DIRECTION OUTPUT ;
    USE SIGNAL ;
    SHAPE ABUTMENT ;
    PORT
      LAYER M3 ;
      RECT 12.807 0.000 12.825 0.054 ;
    END
  END rw0_wd_in[198]
  PIN rw0_wd_in[199]
    DIRECTION OUTPUT ;
    USE SIGNAL ;
    SHAPE ABUTMENT ;
    PORT
      LAYER M3 ;
      RECT 12.987 0.000 13.005 0.054 ;
    END
  END rw0_wd_in[199]
  PIN rw0_wd_in[200]
    DIRECTION OUTPUT ;
    USE SIGNAL ;
    SHAPE ABUTMENT ;
    PORT
      LAYER M3 ;
      RECT 13.167 0.000 13.185 0.054 ;
    END
  END rw0_wd_in[200]
  PIN rw0_wd_in[201]
    DIRECTION OUTPUT ;
    USE SIGNAL ;
    SHAPE ABUTMENT ;
    PORT
      LAYER M3 ;
      RECT 13.347 0.000 13.365 0.054 ;
    END
  END rw0_wd_in[201]
  PIN rw0_wd_in[202]
    DIRECTION OUTPUT ;
    USE SIGNAL ;
    SHAPE ABUTMENT ;
    PORT
      LAYER M3 ;
      RECT 13.527 0.000 13.545 0.054 ;
    END
  END rw0_wd_in[202]
  PIN rw0_wd_in[203]
    DIRECTION OUTPUT ;
    USE SIGNAL ;
    SHAPE ABUTMENT ;
    PORT
      LAYER M3 ;
      RECT 13.707 0.000 13.725 0.054 ;
    END
  END rw0_wd_in[203]
  PIN rw0_wd_in[204]
    DIRECTION OUTPUT ;
    USE SIGNAL ;
    SHAPE ABUTMENT ;
    PORT
      LAYER M3 ;
      RECT 13.887 0.000 13.905 0.054 ;
    END
  END rw0_wd_in[204]
  PIN rw0_wd_in[205]
    DIRECTION OUTPUT ;
    USE SIGNAL ;
    SHAPE ABUTMENT ;
    PORT
      LAYER M3 ;
      RECT 14.067 0.000 14.085 0.054 ;
    END
  END rw0_wd_in[205]
  PIN rw0_wd_in[206]
    DIRECTION OUTPUT ;
    USE SIGNAL ;
    SHAPE ABUTMENT ;
    PORT
      LAYER M3 ;
      RECT 14.247 0.000 14.265 0.054 ;
    END
  END rw0_wd_in[206]
  PIN rw0_wd_in[207]
    DIRECTION OUTPUT ;
    USE SIGNAL ;
    SHAPE ABUTMENT ;
    PORT
      LAYER M3 ;
      RECT 14.427 0.000 14.445 0.054 ;
    END
  END rw0_wd_in[207]
  PIN rw0_wd_in[208]
    DIRECTION OUTPUT ;
    USE SIGNAL ;
    SHAPE ABUTMENT ;
    PORT
      LAYER M3 ;
      RECT 14.607 0.000 14.625 0.054 ;
    END
  END rw0_wd_in[208]
  PIN rw0_wd_in[209]
    DIRECTION OUTPUT ;
    USE SIGNAL ;
    SHAPE ABUTMENT ;
    PORT
      LAYER M3 ;
      RECT 14.787 0.000 14.805 0.054 ;
    END
  END rw0_wd_in[209]
  PIN rw0_wd_in[210]
    DIRECTION OUTPUT ;
    USE SIGNAL ;
    SHAPE ABUTMENT ;
    PORT
      LAYER M3 ;
      RECT 14.967 0.000 14.985 0.054 ;
    END
  END rw0_wd_in[210]
  PIN rw0_wd_in[211]
    DIRECTION OUTPUT ;
    USE SIGNAL ;
    SHAPE ABUTMENT ;
    PORT
      LAYER M3 ;
      RECT 15.147 0.000 15.165 0.054 ;
    END
  END rw0_wd_in[211]
  PIN rw0_wd_in[212]
    DIRECTION OUTPUT ;
    USE SIGNAL ;
    SHAPE ABUTMENT ;
    PORT
      LAYER M3 ;
      RECT 15.327 0.000 15.345 0.054 ;
    END
  END rw0_wd_in[212]
  PIN rw0_wd_in[213]
    DIRECTION OUTPUT ;
    USE SIGNAL ;
    SHAPE ABUTMENT ;
    PORT
      LAYER M3 ;
      RECT 15.507 0.000 15.525 0.054 ;
    END
  END rw0_wd_in[213]
  PIN rw0_wd_in[214]
    DIRECTION OUTPUT ;
    USE SIGNAL ;
    SHAPE ABUTMENT ;
    PORT
      LAYER M3 ;
      RECT 15.687 0.000 15.705 0.054 ;
    END
  END rw0_wd_in[214]
  PIN rw0_wd_in[215]
    DIRECTION OUTPUT ;
    USE SIGNAL ;
    SHAPE ABUTMENT ;
    PORT
      LAYER M3 ;
      RECT 15.867 0.000 15.885 0.054 ;
    END
  END rw0_wd_in[215]
  PIN rw0_wd_in[216]
    DIRECTION OUTPUT ;
    USE SIGNAL ;
    SHAPE ABUTMENT ;
    PORT
      LAYER M3 ;
      RECT 16.047 0.000 16.065 0.054 ;
    END
  END rw0_wd_in[216]
  PIN rw0_wd_in[217]
    DIRECTION OUTPUT ;
    USE SIGNAL ;
    SHAPE ABUTMENT ;
    PORT
      LAYER M3 ;
      RECT 16.227 0.000 16.245 0.054 ;
    END
  END rw0_wd_in[217]
  PIN rw0_wd_in[218]
    DIRECTION OUTPUT ;
    USE SIGNAL ;
    SHAPE ABUTMENT ;
    PORT
      LAYER M3 ;
      RECT 16.407 0.000 16.425 0.054 ;
    END
  END rw0_wd_in[218]
  PIN rw0_wd_in[219]
    DIRECTION OUTPUT ;
    USE SIGNAL ;
    SHAPE ABUTMENT ;
    PORT
      LAYER M3 ;
      RECT 16.587 0.000 16.605 0.054 ;
    END
  END rw0_wd_in[219]
  PIN rw0_wd_in[220]
    DIRECTION OUTPUT ;
    USE SIGNAL ;
    SHAPE ABUTMENT ;
    PORT
      LAYER M3 ;
      RECT 16.767 0.000 16.785 0.054 ;
    END
  END rw0_wd_in[220]
  PIN rw0_wd_in[221]
    DIRECTION OUTPUT ;
    USE SIGNAL ;
    SHAPE ABUTMENT ;
    PORT
      LAYER M3 ;
      RECT 16.947 0.000 16.965 0.054 ;
    END
  END rw0_wd_in[221]
  PIN rw0_wd_in[222]
    DIRECTION OUTPUT ;
    USE SIGNAL ;
    SHAPE ABUTMENT ;
    PORT
      LAYER M3 ;
      RECT 17.127 0.000 17.145 0.054 ;
    END
  END rw0_wd_in[222]
  PIN rw0_wd_in[223]
    DIRECTION OUTPUT ;
    USE SIGNAL ;
    SHAPE ABUTMENT ;
    PORT
      LAYER M3 ;
      RECT 17.307 0.000 17.325 0.054 ;
    END
  END rw0_wd_in[223]
  PIN rw0_wd_in[224]
    DIRECTION OUTPUT ;
    USE SIGNAL ;
    SHAPE ABUTMENT ;
    PORT
      LAYER M3 ;
      RECT 17.487 0.000 17.505 0.054 ;
    END
  END rw0_wd_in[224]
  PIN rw0_wd_in[225]
    DIRECTION OUTPUT ;
    USE SIGNAL ;
    SHAPE ABUTMENT ;
    PORT
      LAYER M3 ;
      RECT 17.667 0.000 17.685 0.054 ;
    END
  END rw0_wd_in[225]
  PIN rw0_wd_in[226]
    DIRECTION OUTPUT ;
    USE SIGNAL ;
    SHAPE ABUTMENT ;
    PORT
      LAYER M3 ;
      RECT 17.847 0.000 17.865 0.054 ;
    END
  END rw0_wd_in[226]
  PIN rw0_wd_in[227]
    DIRECTION OUTPUT ;
    USE SIGNAL ;
    SHAPE ABUTMENT ;
    PORT
      LAYER M3 ;
      RECT 18.027 0.000 18.045 0.054 ;
    END
  END rw0_wd_in[227]
  PIN rw0_wd_in[228]
    DIRECTION OUTPUT ;
    USE SIGNAL ;
    SHAPE ABUTMENT ;
    PORT
      LAYER M3 ;
      RECT 18.207 0.000 18.225 0.054 ;
    END
  END rw0_wd_in[228]
  PIN rw0_wd_in[229]
    DIRECTION OUTPUT ;
    USE SIGNAL ;
    SHAPE ABUTMENT ;
    PORT
      LAYER M3 ;
      RECT 18.387 0.000 18.405 0.054 ;
    END
  END rw0_wd_in[229]
  PIN rw0_wd_in[230]
    DIRECTION OUTPUT ;
    USE SIGNAL ;
    SHAPE ABUTMENT ;
    PORT
      LAYER M3 ;
      RECT 18.567 0.000 18.585 0.054 ;
    END
  END rw0_wd_in[230]
  PIN rw0_wd_in[231]
    DIRECTION OUTPUT ;
    USE SIGNAL ;
    SHAPE ABUTMENT ;
    PORT
      LAYER M3 ;
      RECT 18.747 0.000 18.765 0.054 ;
    END
  END rw0_wd_in[231]
  PIN rw0_wd_in[232]
    DIRECTION OUTPUT ;
    USE SIGNAL ;
    SHAPE ABUTMENT ;
    PORT
      LAYER M3 ;
      RECT 18.927 0.000 18.945 0.054 ;
    END
  END rw0_wd_in[232]
  PIN rw0_wd_in[233]
    DIRECTION OUTPUT ;
    USE SIGNAL ;
    SHAPE ABUTMENT ;
    PORT
      LAYER M3 ;
      RECT 19.107 0.000 19.125 0.054 ;
    END
  END rw0_wd_in[233]
  PIN rw0_wd_in[234]
    DIRECTION OUTPUT ;
    USE SIGNAL ;
    SHAPE ABUTMENT ;
    PORT
      LAYER M3 ;
      RECT 19.287 0.000 19.305 0.054 ;
    END
  END rw0_wd_in[234]
  PIN rw0_wd_in[235]
    DIRECTION OUTPUT ;
    USE SIGNAL ;
    SHAPE ABUTMENT ;
    PORT
      LAYER M3 ;
      RECT 19.467 0.000 19.485 0.054 ;
    END
  END rw0_wd_in[235]
  PIN rw0_wd_in[236]
    DIRECTION OUTPUT ;
    USE SIGNAL ;
    SHAPE ABUTMENT ;
    PORT
      LAYER M3 ;
      RECT 19.647 0.000 19.665 0.054 ;
    END
  END rw0_wd_in[236]
  PIN rw0_wd_in[237]
    DIRECTION OUTPUT ;
    USE SIGNAL ;
    SHAPE ABUTMENT ;
    PORT
      LAYER M3 ;
      RECT 19.827 0.000 19.845 0.054 ;
    END
  END rw0_wd_in[237]
  PIN rw0_wd_in[238]
    DIRECTION OUTPUT ;
    USE SIGNAL ;
    SHAPE ABUTMENT ;
    PORT
      LAYER M3 ;
      RECT 20.007 0.000 20.025 0.054 ;
    END
  END rw0_wd_in[238]
  PIN rw0_wd_in[239]
    DIRECTION OUTPUT ;
    USE SIGNAL ;
    SHAPE ABUTMENT ;
    PORT
      LAYER M3 ;
      RECT 20.187 0.000 20.205 0.054 ;
    END
  END rw0_wd_in[239]
  PIN rw0_wd_in[240]
    DIRECTION OUTPUT ;
    USE SIGNAL ;
    SHAPE ABUTMENT ;
    PORT
      LAYER M3 ;
      RECT 20.367 0.000 20.385 0.054 ;
    END
  END rw0_wd_in[240]
  PIN rw0_wd_in[241]
    DIRECTION OUTPUT ;
    USE SIGNAL ;
    SHAPE ABUTMENT ;
    PORT
      LAYER M3 ;
      RECT 20.547 0.000 20.565 0.054 ;
    END
  END rw0_wd_in[241]
  PIN rw0_wd_in[242]
    DIRECTION OUTPUT ;
    USE SIGNAL ;
    SHAPE ABUTMENT ;
    PORT
      LAYER M3 ;
      RECT 20.727 0.000 20.745 0.054 ;
    END
  END rw0_wd_in[242]
  PIN rw0_wd_in[243]
    DIRECTION OUTPUT ;
    USE SIGNAL ;
    SHAPE ABUTMENT ;
    PORT
      LAYER M3 ;
      RECT 20.907 0.000 20.925 0.054 ;
    END
  END rw0_wd_in[243]
  PIN rw0_wd_in[244]
    DIRECTION OUTPUT ;
    USE SIGNAL ;
    SHAPE ABUTMENT ;
    PORT
      LAYER M3 ;
      RECT 21.087 0.000 21.105 0.054 ;
    END
  END rw0_wd_in[244]
  PIN rw0_wd_in[245]
    DIRECTION OUTPUT ;
    USE SIGNAL ;
    SHAPE ABUTMENT ;
    PORT
      LAYER M3 ;
      RECT 21.267 0.000 21.285 0.054 ;
    END
  END rw0_wd_in[245]
  PIN rw0_wd_in[246]
    DIRECTION OUTPUT ;
    USE SIGNAL ;
    SHAPE ABUTMENT ;
    PORT
      LAYER M3 ;
      RECT 21.447 0.000 21.465 0.054 ;
    END
  END rw0_wd_in[246]
  PIN rw0_wd_in[247]
    DIRECTION OUTPUT ;
    USE SIGNAL ;
    SHAPE ABUTMENT ;
    PORT
      LAYER M3 ;
      RECT 21.627 0.000 21.645 0.054 ;
    END
  END rw0_wd_in[247]
  PIN rw0_wd_in[248]
    DIRECTION OUTPUT ;
    USE SIGNAL ;
    SHAPE ABUTMENT ;
    PORT
      LAYER M3 ;
      RECT 21.807 0.000 21.825 0.054 ;
    END
  END rw0_wd_in[248]
  PIN rw0_wd_in[249]
    DIRECTION OUTPUT ;
    USE SIGNAL ;
    SHAPE ABUTMENT ;
    PORT
      LAYER M3 ;
      RECT 21.987 0.000 22.005 0.054 ;
    END
  END rw0_wd_in[249]
  PIN rw0_wd_in[250]
    DIRECTION OUTPUT ;
    USE SIGNAL ;
    SHAPE ABUTMENT ;
    PORT
      LAYER M3 ;
      RECT 22.167 0.000 22.185 0.054 ;
    END
  END rw0_wd_in[250]
  PIN rw0_wd_in[251]
    DIRECTION OUTPUT ;
    USE SIGNAL ;
    SHAPE ABUTMENT ;
    PORT
      LAYER M3 ;
      RECT 22.347 0.000 22.365 0.054 ;
    END
  END rw0_wd_in[251]
  PIN rw0_wd_in[252]
    DIRECTION OUTPUT ;
    USE SIGNAL ;
    SHAPE ABUTMENT ;
    PORT
      LAYER M3 ;
      RECT 22.527 0.000 22.545 0.054 ;
    END
  END rw0_wd_in[252]
  PIN rw0_wd_in[253]
    DIRECTION OUTPUT ;
    USE SIGNAL ;
    SHAPE ABUTMENT ;
    PORT
      LAYER M3 ;
      RECT 22.707 0.000 22.725 0.054 ;
    END
  END rw0_wd_in[253]
  PIN rw0_wd_in[254]
    DIRECTION OUTPUT ;
    USE SIGNAL ;
    SHAPE ABUTMENT ;
    PORT
      LAYER M3 ;
      RECT 22.887 0.000 22.905 0.054 ;
    END
  END rw0_wd_in[254]
  PIN rw0_wd_in[255]
    DIRECTION OUTPUT ;
    USE SIGNAL ;
    SHAPE ABUTMENT ;
    PORT
      LAYER M3 ;
      RECT 23.067 0.000 23.085 0.054 ;
    END
  END rw0_wd_in[255]
  PIN rw0_rd_out[0]
    DIRECTION OUTPUT ;
    USE SIGNAL ;
    SHAPE ABUTMENT ;
    PORT
      LAYER M3 ;
      RECT 23.247 0.000 23.265 0.054 ;
    END
  END rw0_rd_out[0]
  PIN rw0_rd_out[1]
    DIRECTION OUTPUT ;
    USE SIGNAL ;
    SHAPE ABUTMENT ;
    PORT
      LAYER M3 ;
      RECT 23.427 0.000 23.445 0.054 ;
    END
  END rw0_rd_out[1]
  PIN rw0_rd_out[2]
    DIRECTION OUTPUT ;
    USE SIGNAL ;
    SHAPE ABUTMENT ;
    PORT
      LAYER M3 ;
      RECT 23.607 0.000 23.625 0.054 ;
    END
  END rw0_rd_out[2]
  PIN rw0_rd_out[3]
    DIRECTION OUTPUT ;
    USE SIGNAL ;
    SHAPE ABUTMENT ;
    PORT
      LAYER M3 ;
      RECT 23.787 0.000 23.805 0.054 ;
    END
  END rw0_rd_out[3]
  PIN rw0_rd_out[4]
    DIRECTION OUTPUT ;
    USE SIGNAL ;
    SHAPE ABUTMENT ;
    PORT
      LAYER M3 ;
      RECT 23.967 0.000 23.985 0.054 ;
    END
  END rw0_rd_out[4]
  PIN rw0_rd_out[5]
    DIRECTION OUTPUT ;
    USE SIGNAL ;
    SHAPE ABUTMENT ;
    PORT
      LAYER M3 ;
      RECT 24.147 0.000 24.165 0.054 ;
    END
  END rw0_rd_out[5]
  PIN rw0_rd_out[6]
    DIRECTION OUTPUT ;
    USE SIGNAL ;
    SHAPE ABUTMENT ;
    PORT
      LAYER M3 ;
      RECT 24.327 0.000 24.345 0.054 ;
    END
  END rw0_rd_out[6]
  PIN rw0_rd_out[7]
    DIRECTION OUTPUT ;
    USE SIGNAL ;
    SHAPE ABUTMENT ;
    PORT
      LAYER M3 ;
      RECT 24.507 0.000 24.525 0.054 ;
    END
  END rw0_rd_out[7]
  PIN rw0_rd_out[8]
    DIRECTION OUTPUT ;
    USE SIGNAL ;
    SHAPE ABUTMENT ;
    PORT
      LAYER M3 ;
      RECT 24.687 0.000 24.705 0.054 ;
    END
  END rw0_rd_out[8]
  PIN rw0_rd_out[9]
    DIRECTION OUTPUT ;
    USE SIGNAL ;
    SHAPE ABUTMENT ;
    PORT
      LAYER M3 ;
      RECT 24.867 0.000 24.885 0.054 ;
    END
  END rw0_rd_out[9]
  PIN rw0_rd_out[10]
    DIRECTION OUTPUT ;
    USE SIGNAL ;
    SHAPE ABUTMENT ;
    PORT
      LAYER M3 ;
      RECT 25.047 0.000 25.065 0.054 ;
    END
  END rw0_rd_out[10]
  PIN rw0_rd_out[11]
    DIRECTION OUTPUT ;
    USE SIGNAL ;
    SHAPE ABUTMENT ;
    PORT
      LAYER M3 ;
      RECT 25.227 0.000 25.245 0.054 ;
    END
  END rw0_rd_out[11]
  PIN rw0_rd_out[12]
    DIRECTION OUTPUT ;
    USE SIGNAL ;
    SHAPE ABUTMENT ;
    PORT
      LAYER M3 ;
      RECT 25.407 0.000 25.425 0.054 ;
    END
  END rw0_rd_out[12]
  PIN rw0_rd_out[13]
    DIRECTION OUTPUT ;
    USE SIGNAL ;
    SHAPE ABUTMENT ;
    PORT
      LAYER M3 ;
      RECT 25.587 0.000 25.605 0.054 ;
    END
  END rw0_rd_out[13]
  PIN rw0_rd_out[14]
    DIRECTION OUTPUT ;
    USE SIGNAL ;
    SHAPE ABUTMENT ;
    PORT
      LAYER M3 ;
      RECT 25.767 0.000 25.785 0.054 ;
    END
  END rw0_rd_out[14]
  PIN rw0_rd_out[15]
    DIRECTION OUTPUT ;
    USE SIGNAL ;
    SHAPE ABUTMENT ;
    PORT
      LAYER M3 ;
      RECT 25.947 0.000 25.965 0.054 ;
    END
  END rw0_rd_out[15]
  PIN rw0_rd_out[16]
    DIRECTION OUTPUT ;
    USE SIGNAL ;
    SHAPE ABUTMENT ;
    PORT
      LAYER M3 ;
      RECT 26.127 0.000 26.145 0.054 ;
    END
  END rw0_rd_out[16]
  PIN rw0_rd_out[17]
    DIRECTION OUTPUT ;
    USE SIGNAL ;
    SHAPE ABUTMENT ;
    PORT
      LAYER M3 ;
      RECT 26.307 0.000 26.325 0.054 ;
    END
  END rw0_rd_out[17]
  PIN rw0_rd_out[18]
    DIRECTION OUTPUT ;
    USE SIGNAL ;
    SHAPE ABUTMENT ;
    PORT
      LAYER M3 ;
      RECT 26.487 0.000 26.505 0.054 ;
    END
  END rw0_rd_out[18]
  PIN rw0_rd_out[19]
    DIRECTION OUTPUT ;
    USE SIGNAL ;
    SHAPE ABUTMENT ;
    PORT
      LAYER M3 ;
      RECT 26.667 0.000 26.685 0.054 ;
    END
  END rw0_rd_out[19]
  PIN rw0_rd_out[20]
    DIRECTION OUTPUT ;
    USE SIGNAL ;
    SHAPE ABUTMENT ;
    PORT
      LAYER M3 ;
      RECT 26.847 0.000 26.865 0.054 ;
    END
  END rw0_rd_out[20]
  PIN rw0_rd_out[21]
    DIRECTION OUTPUT ;
    USE SIGNAL ;
    SHAPE ABUTMENT ;
    PORT
      LAYER M3 ;
      RECT 27.027 0.000 27.045 0.054 ;
    END
  END rw0_rd_out[21]
  PIN rw0_rd_out[22]
    DIRECTION OUTPUT ;
    USE SIGNAL ;
    SHAPE ABUTMENT ;
    PORT
      LAYER M3 ;
      RECT 27.207 0.000 27.225 0.054 ;
    END
  END rw0_rd_out[22]
  PIN rw0_rd_out[23]
    DIRECTION OUTPUT ;
    USE SIGNAL ;
    SHAPE ABUTMENT ;
    PORT
      LAYER M3 ;
      RECT 27.387 0.000 27.405 0.054 ;
    END
  END rw0_rd_out[23]
  PIN rw0_rd_out[24]
    DIRECTION OUTPUT ;
    USE SIGNAL ;
    SHAPE ABUTMENT ;
    PORT
      LAYER M3 ;
      RECT 27.567 0.000 27.585 0.054 ;
    END
  END rw0_rd_out[24]
  PIN rw0_rd_out[25]
    DIRECTION OUTPUT ;
    USE SIGNAL ;
    SHAPE ABUTMENT ;
    PORT
      LAYER M3 ;
      RECT 27.747 0.000 27.765 0.054 ;
    END
  END rw0_rd_out[25]
  PIN rw0_rd_out[26]
    DIRECTION OUTPUT ;
    USE SIGNAL ;
    SHAPE ABUTMENT ;
    PORT
      LAYER M3 ;
      RECT 27.927 0.000 27.945 0.054 ;
    END
  END rw0_rd_out[26]
  PIN rw0_rd_out[27]
    DIRECTION OUTPUT ;
    USE SIGNAL ;
    SHAPE ABUTMENT ;
    PORT
      LAYER M3 ;
      RECT 28.107 0.000 28.125 0.054 ;
    END
  END rw0_rd_out[27]
  PIN rw0_rd_out[28]
    DIRECTION OUTPUT ;
    USE SIGNAL ;
    SHAPE ABUTMENT ;
    PORT
      LAYER M3 ;
      RECT 28.287 0.000 28.305 0.054 ;
    END
  END rw0_rd_out[28]
  PIN rw0_rd_out[29]
    DIRECTION OUTPUT ;
    USE SIGNAL ;
    SHAPE ABUTMENT ;
    PORT
      LAYER M3 ;
      RECT 28.467 0.000 28.485 0.054 ;
    END
  END rw0_rd_out[29]
  PIN rw0_rd_out[30]
    DIRECTION OUTPUT ;
    USE SIGNAL ;
    SHAPE ABUTMENT ;
    PORT
      LAYER M3 ;
      RECT 28.647 0.000 28.665 0.054 ;
    END
  END rw0_rd_out[30]
  PIN rw0_rd_out[31]
    DIRECTION OUTPUT ;
    USE SIGNAL ;
    SHAPE ABUTMENT ;
    PORT
      LAYER M3 ;
      RECT 28.827 0.000 28.845 0.054 ;
    END
  END rw0_rd_out[31]
  PIN rw0_rd_out[32]
    DIRECTION OUTPUT ;
    USE SIGNAL ;
    SHAPE ABUTMENT ;
    PORT
      LAYER M3 ;
      RECT 29.007 0.000 29.025 0.054 ;
    END
  END rw0_rd_out[32]
  PIN rw0_rd_out[33]
    DIRECTION OUTPUT ;
    USE SIGNAL ;
    SHAPE ABUTMENT ;
    PORT
      LAYER M3 ;
      RECT 29.187 0.000 29.205 0.054 ;
    END
  END rw0_rd_out[33]
  PIN rw0_rd_out[34]
    DIRECTION OUTPUT ;
    USE SIGNAL ;
    SHAPE ABUTMENT ;
    PORT
      LAYER M3 ;
      RECT 29.367 0.000 29.385 0.054 ;
    END
  END rw0_rd_out[34]
  PIN rw0_rd_out[35]
    DIRECTION OUTPUT ;
    USE SIGNAL ;
    SHAPE ABUTMENT ;
    PORT
      LAYER M3 ;
      RECT 29.547 0.000 29.565 0.054 ;
    END
  END rw0_rd_out[35]
  PIN rw0_rd_out[36]
    DIRECTION OUTPUT ;
    USE SIGNAL ;
    SHAPE ABUTMENT ;
    PORT
      LAYER M3 ;
      RECT 29.727 0.000 29.745 0.054 ;
    END
  END rw0_rd_out[36]
  PIN rw0_rd_out[37]
    DIRECTION OUTPUT ;
    USE SIGNAL ;
    SHAPE ABUTMENT ;
    PORT
      LAYER M3 ;
      RECT 29.907 0.000 29.925 0.054 ;
    END
  END rw0_rd_out[37]
  PIN rw0_rd_out[38]
    DIRECTION OUTPUT ;
    USE SIGNAL ;
    SHAPE ABUTMENT ;
    PORT
      LAYER M3 ;
      RECT 30.087 0.000 30.105 0.054 ;
    END
  END rw0_rd_out[38]
  PIN rw0_rd_out[39]
    DIRECTION OUTPUT ;
    USE SIGNAL ;
    SHAPE ABUTMENT ;
    PORT
      LAYER M3 ;
      RECT 30.267 0.000 30.285 0.054 ;
    END
  END rw0_rd_out[39]
  PIN rw0_rd_out[40]
    DIRECTION OUTPUT ;
    USE SIGNAL ;
    SHAPE ABUTMENT ;
    PORT
      LAYER M3 ;
      RECT 30.447 0.000 30.465 0.054 ;
    END
  END rw0_rd_out[40]
  PIN rw0_rd_out[41]
    DIRECTION OUTPUT ;
    USE SIGNAL ;
    SHAPE ABUTMENT ;
    PORT
      LAYER M3 ;
      RECT 30.627 0.000 30.645 0.054 ;
    END
  END rw0_rd_out[41]
  PIN rw0_rd_out[42]
    DIRECTION OUTPUT ;
    USE SIGNAL ;
    SHAPE ABUTMENT ;
    PORT
      LAYER M3 ;
      RECT 30.807 0.000 30.825 0.054 ;
    END
  END rw0_rd_out[42]
  PIN rw0_rd_out[43]
    DIRECTION OUTPUT ;
    USE SIGNAL ;
    SHAPE ABUTMENT ;
    PORT
      LAYER M3 ;
      RECT 30.987 0.000 31.005 0.054 ;
    END
  END rw0_rd_out[43]
  PIN rw0_rd_out[44]
    DIRECTION OUTPUT ;
    USE SIGNAL ;
    SHAPE ABUTMENT ;
    PORT
      LAYER M3 ;
      RECT 31.167 0.000 31.185 0.054 ;
    END
  END rw0_rd_out[44]
  PIN rw0_rd_out[45]
    DIRECTION OUTPUT ;
    USE SIGNAL ;
    SHAPE ABUTMENT ;
    PORT
      LAYER M3 ;
      RECT 31.347 0.000 31.365 0.054 ;
    END
  END rw0_rd_out[45]
  PIN rw0_rd_out[46]
    DIRECTION OUTPUT ;
    USE SIGNAL ;
    SHAPE ABUTMENT ;
    PORT
      LAYER M3 ;
      RECT 31.527 0.000 31.545 0.054 ;
    END
  END rw0_rd_out[46]
  PIN rw0_rd_out[47]
    DIRECTION OUTPUT ;
    USE SIGNAL ;
    SHAPE ABUTMENT ;
    PORT
      LAYER M3 ;
      RECT 31.707 0.000 31.725 0.054 ;
    END
  END rw0_rd_out[47]
  PIN rw0_rd_out[48]
    DIRECTION OUTPUT ;
    USE SIGNAL ;
    SHAPE ABUTMENT ;
    PORT
      LAYER M3 ;
      RECT 31.887 0.000 31.905 0.054 ;
    END
  END rw0_rd_out[48]
  PIN rw0_rd_out[49]
    DIRECTION OUTPUT ;
    USE SIGNAL ;
    SHAPE ABUTMENT ;
    PORT
      LAYER M3 ;
      RECT 32.067 0.000 32.085 0.054 ;
    END
  END rw0_rd_out[49]
  PIN rw0_rd_out[50]
    DIRECTION OUTPUT ;
    USE SIGNAL ;
    SHAPE ABUTMENT ;
    PORT
      LAYER M3 ;
      RECT 32.247 0.000 32.265 0.054 ;
    END
  END rw0_rd_out[50]
  PIN rw0_rd_out[51]
    DIRECTION OUTPUT ;
    USE SIGNAL ;
    SHAPE ABUTMENT ;
    PORT
      LAYER M3 ;
      RECT 32.427 0.000 32.445 0.054 ;
    END
  END rw0_rd_out[51]
  PIN rw0_rd_out[52]
    DIRECTION OUTPUT ;
    USE SIGNAL ;
    SHAPE ABUTMENT ;
    PORT
      LAYER M3 ;
      RECT 32.607 0.000 32.625 0.054 ;
    END
  END rw0_rd_out[52]
  PIN rw0_rd_out[53]
    DIRECTION OUTPUT ;
    USE SIGNAL ;
    SHAPE ABUTMENT ;
    PORT
      LAYER M3 ;
      RECT 32.787 0.000 32.805 0.054 ;
    END
  END rw0_rd_out[53]
  PIN rw0_rd_out[54]
    DIRECTION OUTPUT ;
    USE SIGNAL ;
    SHAPE ABUTMENT ;
    PORT
      LAYER M3 ;
      RECT 32.967 0.000 32.985 0.054 ;
    END
  END rw0_rd_out[54]
  PIN rw0_rd_out[55]
    DIRECTION OUTPUT ;
    USE SIGNAL ;
    SHAPE ABUTMENT ;
    PORT
      LAYER M3 ;
      RECT 33.147 0.000 33.165 0.054 ;
    END
  END rw0_rd_out[55]
  PIN rw0_rd_out[56]
    DIRECTION OUTPUT ;
    USE SIGNAL ;
    SHAPE ABUTMENT ;
    PORT
      LAYER M3 ;
      RECT 33.327 0.000 33.345 0.054 ;
    END
  END rw0_rd_out[56]
  PIN rw0_rd_out[57]
    DIRECTION OUTPUT ;
    USE SIGNAL ;
    SHAPE ABUTMENT ;
    PORT
      LAYER M3 ;
      RECT 33.507 0.000 33.525 0.054 ;
    END
  END rw0_rd_out[57]
  PIN rw0_rd_out[58]
    DIRECTION OUTPUT ;
    USE SIGNAL ;
    SHAPE ABUTMENT ;
    PORT
      LAYER M3 ;
      RECT 33.687 0.000 33.705 0.054 ;
    END
  END rw0_rd_out[58]
  PIN rw0_rd_out[59]
    DIRECTION OUTPUT ;
    USE SIGNAL ;
    SHAPE ABUTMENT ;
    PORT
      LAYER M3 ;
      RECT 33.867 0.000 33.885 0.054 ;
    END
  END rw0_rd_out[59]
  PIN rw0_rd_out[60]
    DIRECTION OUTPUT ;
    USE SIGNAL ;
    SHAPE ABUTMENT ;
    PORT
      LAYER M3 ;
      RECT 34.047 0.000 34.065 0.054 ;
    END
  END rw0_rd_out[60]
  PIN rw0_rd_out[61]
    DIRECTION OUTPUT ;
    USE SIGNAL ;
    SHAPE ABUTMENT ;
    PORT
      LAYER M3 ;
      RECT 34.227 0.000 34.245 0.054 ;
    END
  END rw0_rd_out[61]
  PIN rw0_rd_out[62]
    DIRECTION OUTPUT ;
    USE SIGNAL ;
    SHAPE ABUTMENT ;
    PORT
      LAYER M3 ;
      RECT 34.407 0.000 34.425 0.054 ;
    END
  END rw0_rd_out[62]
  PIN rw0_rd_out[63]
    DIRECTION OUTPUT ;
    USE SIGNAL ;
    SHAPE ABUTMENT ;
    PORT
      LAYER M3 ;
      RECT 34.587 0.000 34.605 0.054 ;
    END
  END rw0_rd_out[63]
  PIN rw0_rd_out[64]
    DIRECTION OUTPUT ;
    USE SIGNAL ;
    SHAPE ABUTMENT ;
    PORT
      LAYER M3 ;
      RECT 34.767 0.000 34.785 0.054 ;
    END
  END rw0_rd_out[64]
  PIN rw0_rd_out[65]
    DIRECTION OUTPUT ;
    USE SIGNAL ;
    SHAPE ABUTMENT ;
    PORT
      LAYER M3 ;
      RECT 34.947 0.000 34.965 0.054 ;
    END
  END rw0_rd_out[65]
  PIN rw0_rd_out[66]
    DIRECTION OUTPUT ;
    USE SIGNAL ;
    SHAPE ABUTMENT ;
    PORT
      LAYER M3 ;
      RECT 35.127 0.000 35.145 0.054 ;
    END
  END rw0_rd_out[66]
  PIN rw0_rd_out[67]
    DIRECTION OUTPUT ;
    USE SIGNAL ;
    SHAPE ABUTMENT ;
    PORT
      LAYER M3 ;
      RECT 35.307 0.000 35.325 0.054 ;
    END
  END rw0_rd_out[67]
  PIN rw0_rd_out[68]
    DIRECTION OUTPUT ;
    USE SIGNAL ;
    SHAPE ABUTMENT ;
    PORT
      LAYER M3 ;
      RECT 35.487 0.000 35.505 0.054 ;
    END
  END rw0_rd_out[68]
  PIN rw0_rd_out[69]
    DIRECTION OUTPUT ;
    USE SIGNAL ;
    SHAPE ABUTMENT ;
    PORT
      LAYER M3 ;
      RECT 35.667 0.000 35.685 0.054 ;
    END
  END rw0_rd_out[69]
  PIN rw0_rd_out[70]
    DIRECTION OUTPUT ;
    USE SIGNAL ;
    SHAPE ABUTMENT ;
    PORT
      LAYER M3 ;
      RECT 35.847 0.000 35.865 0.054 ;
    END
  END rw0_rd_out[70]
  PIN rw0_rd_out[71]
    DIRECTION OUTPUT ;
    USE SIGNAL ;
    SHAPE ABUTMENT ;
    PORT
      LAYER M3 ;
      RECT 36.027 0.000 36.045 0.054 ;
    END
  END rw0_rd_out[71]
  PIN rw0_rd_out[72]
    DIRECTION OUTPUT ;
    USE SIGNAL ;
    SHAPE ABUTMENT ;
    PORT
      LAYER M3 ;
      RECT 36.207 0.000 36.225 0.054 ;
    END
  END rw0_rd_out[72]
  PIN rw0_rd_out[73]
    DIRECTION OUTPUT ;
    USE SIGNAL ;
    SHAPE ABUTMENT ;
    PORT
      LAYER M3 ;
      RECT 36.387 0.000 36.405 0.054 ;
    END
  END rw0_rd_out[73]
  PIN rw0_rd_out[74]
    DIRECTION OUTPUT ;
    USE SIGNAL ;
    SHAPE ABUTMENT ;
    PORT
      LAYER M3 ;
      RECT 36.567 0.000 36.585 0.054 ;
    END
  END rw0_rd_out[74]
  PIN rw0_rd_out[75]
    DIRECTION OUTPUT ;
    USE SIGNAL ;
    SHAPE ABUTMENT ;
    PORT
      LAYER M3 ;
      RECT 36.747 0.000 36.765 0.054 ;
    END
  END rw0_rd_out[75]
  PIN rw0_rd_out[76]
    DIRECTION OUTPUT ;
    USE SIGNAL ;
    SHAPE ABUTMENT ;
    PORT
      LAYER M3 ;
      RECT 36.927 0.000 36.945 0.054 ;
    END
  END rw0_rd_out[76]
  PIN rw0_rd_out[77]
    DIRECTION OUTPUT ;
    USE SIGNAL ;
    SHAPE ABUTMENT ;
    PORT
      LAYER M3 ;
      RECT 37.107 0.000 37.125 0.054 ;
    END
  END rw0_rd_out[77]
  PIN rw0_rd_out[78]
    DIRECTION OUTPUT ;
    USE SIGNAL ;
    SHAPE ABUTMENT ;
    PORT
      LAYER M3 ;
      RECT 37.287 0.000 37.305 0.054 ;
    END
  END rw0_rd_out[78]
  PIN rw0_rd_out[79]
    DIRECTION OUTPUT ;
    USE SIGNAL ;
    SHAPE ABUTMENT ;
    PORT
      LAYER M3 ;
      RECT 37.467 0.000 37.485 0.054 ;
    END
  END rw0_rd_out[79]
  PIN rw0_rd_out[80]
    DIRECTION OUTPUT ;
    USE SIGNAL ;
    SHAPE ABUTMENT ;
    PORT
      LAYER M3 ;
      RECT 37.647 0.000 37.665 0.054 ;
    END
  END rw0_rd_out[80]
  PIN rw0_rd_out[81]
    DIRECTION OUTPUT ;
    USE SIGNAL ;
    SHAPE ABUTMENT ;
    PORT
      LAYER M3 ;
      RECT 37.827 0.000 37.845 0.054 ;
    END
  END rw0_rd_out[81]
  PIN rw0_rd_out[82]
    DIRECTION OUTPUT ;
    USE SIGNAL ;
    SHAPE ABUTMENT ;
    PORT
      LAYER M3 ;
      RECT 38.007 0.000 38.025 0.054 ;
    END
  END rw0_rd_out[82]
  PIN rw0_rd_out[83]
    DIRECTION OUTPUT ;
    USE SIGNAL ;
    SHAPE ABUTMENT ;
    PORT
      LAYER M3 ;
      RECT 38.187 0.000 38.205 0.054 ;
    END
  END rw0_rd_out[83]
  PIN rw0_rd_out[84]
    DIRECTION OUTPUT ;
    USE SIGNAL ;
    SHAPE ABUTMENT ;
    PORT
      LAYER M3 ;
      RECT 38.367 0.000 38.385 0.054 ;
    END
  END rw0_rd_out[84]
  PIN rw0_rd_out[85]
    DIRECTION OUTPUT ;
    USE SIGNAL ;
    SHAPE ABUTMENT ;
    PORT
      LAYER M3 ;
      RECT 38.547 0.000 38.565 0.054 ;
    END
  END rw0_rd_out[85]
  PIN rw0_rd_out[86]
    DIRECTION OUTPUT ;
    USE SIGNAL ;
    SHAPE ABUTMENT ;
    PORT
      LAYER M3 ;
      RECT 38.727 0.000 38.745 0.054 ;
    END
  END rw0_rd_out[86]
  PIN rw0_rd_out[87]
    DIRECTION OUTPUT ;
    USE SIGNAL ;
    SHAPE ABUTMENT ;
    PORT
      LAYER M3 ;
      RECT 38.907 0.000 38.925 0.054 ;
    END
  END rw0_rd_out[87]
  PIN rw0_rd_out[88]
    DIRECTION OUTPUT ;
    USE SIGNAL ;
    SHAPE ABUTMENT ;
    PORT
      LAYER M3 ;
      RECT 39.087 0.000 39.105 0.054 ;
    END
  END rw0_rd_out[88]
  PIN rw0_rd_out[89]
    DIRECTION OUTPUT ;
    USE SIGNAL ;
    SHAPE ABUTMENT ;
    PORT
      LAYER M3 ;
      RECT 39.267 0.000 39.285 0.054 ;
    END
  END rw0_rd_out[89]
  PIN rw0_rd_out[90]
    DIRECTION OUTPUT ;
    USE SIGNAL ;
    SHAPE ABUTMENT ;
    PORT
      LAYER M3 ;
      RECT 39.447 0.000 39.465 0.054 ;
    END
  END rw0_rd_out[90]
  PIN rw0_rd_out[91]
    DIRECTION OUTPUT ;
    USE SIGNAL ;
    SHAPE ABUTMENT ;
    PORT
      LAYER M3 ;
      RECT 39.627 0.000 39.645 0.054 ;
    END
  END rw0_rd_out[91]
  PIN rw0_rd_out[92]
    DIRECTION OUTPUT ;
    USE SIGNAL ;
    SHAPE ABUTMENT ;
    PORT
      LAYER M3 ;
      RECT 39.807 0.000 39.825 0.054 ;
    END
  END rw0_rd_out[92]
  PIN rw0_rd_out[93]
    DIRECTION OUTPUT ;
    USE SIGNAL ;
    SHAPE ABUTMENT ;
    PORT
      LAYER M3 ;
      RECT 39.987 0.000 40.005 0.054 ;
    END
  END rw0_rd_out[93]
  PIN rw0_rd_out[94]
    DIRECTION OUTPUT ;
    USE SIGNAL ;
    SHAPE ABUTMENT ;
    PORT
      LAYER M3 ;
      RECT 40.167 0.000 40.185 0.054 ;
    END
  END rw0_rd_out[94]
  PIN rw0_rd_out[95]
    DIRECTION OUTPUT ;
    USE SIGNAL ;
    SHAPE ABUTMENT ;
    PORT
      LAYER M3 ;
      RECT 40.347 0.000 40.365 0.054 ;
    END
  END rw0_rd_out[95]
  PIN rw0_rd_out[96]
    DIRECTION OUTPUT ;
    USE SIGNAL ;
    SHAPE ABUTMENT ;
    PORT
      LAYER M3 ;
      RECT 40.527 0.000 40.545 0.054 ;
    END
  END rw0_rd_out[96]
  PIN rw0_rd_out[97]
    DIRECTION OUTPUT ;
    USE SIGNAL ;
    SHAPE ABUTMENT ;
    PORT
      LAYER M3 ;
      RECT 40.707 0.000 40.725 0.054 ;
    END
  END rw0_rd_out[97]
  PIN rw0_rd_out[98]
    DIRECTION OUTPUT ;
    USE SIGNAL ;
    SHAPE ABUTMENT ;
    PORT
      LAYER M3 ;
      RECT 40.887 0.000 40.905 0.054 ;
    END
  END rw0_rd_out[98]
  PIN rw0_rd_out[99]
    DIRECTION OUTPUT ;
    USE SIGNAL ;
    SHAPE ABUTMENT ;
    PORT
      LAYER M3 ;
      RECT 41.067 0.000 41.085 0.054 ;
    END
  END rw0_rd_out[99]
  PIN rw0_rd_out[100]
    DIRECTION OUTPUT ;
    USE SIGNAL ;
    SHAPE ABUTMENT ;
    PORT
      LAYER M3 ;
      RECT 41.247 0.000 41.265 0.054 ;
    END
  END rw0_rd_out[100]
  PIN rw0_rd_out[101]
    DIRECTION OUTPUT ;
    USE SIGNAL ;
    SHAPE ABUTMENT ;
    PORT
      LAYER M3 ;
      RECT 41.427 0.000 41.445 0.054 ;
    END
  END rw0_rd_out[101]
  PIN rw0_rd_out[102]
    DIRECTION OUTPUT ;
    USE SIGNAL ;
    SHAPE ABUTMENT ;
    PORT
      LAYER M3 ;
      RECT 41.607 0.000 41.625 0.054 ;
    END
  END rw0_rd_out[102]
  PIN rw0_rd_out[103]
    DIRECTION OUTPUT ;
    USE SIGNAL ;
    SHAPE ABUTMENT ;
    PORT
      LAYER M3 ;
      RECT 41.787 0.000 41.805 0.054 ;
    END
  END rw0_rd_out[103]
  PIN rw0_rd_out[104]
    DIRECTION OUTPUT ;
    USE SIGNAL ;
    SHAPE ABUTMENT ;
    PORT
      LAYER M3 ;
      RECT 41.967 0.000 41.985 0.054 ;
    END
  END rw0_rd_out[104]
  PIN rw0_rd_out[105]
    DIRECTION OUTPUT ;
    USE SIGNAL ;
    SHAPE ABUTMENT ;
    PORT
      LAYER M3 ;
      RECT 42.147 0.000 42.165 0.054 ;
    END
  END rw0_rd_out[105]
  PIN rw0_rd_out[106]
    DIRECTION OUTPUT ;
    USE SIGNAL ;
    SHAPE ABUTMENT ;
    PORT
      LAYER M3 ;
      RECT 42.327 0.000 42.345 0.054 ;
    END
  END rw0_rd_out[106]
  PIN rw0_rd_out[107]
    DIRECTION OUTPUT ;
    USE SIGNAL ;
    SHAPE ABUTMENT ;
    PORT
      LAYER M3 ;
      RECT 42.507 0.000 42.525 0.054 ;
    END
  END rw0_rd_out[107]
  PIN rw0_rd_out[108]
    DIRECTION OUTPUT ;
    USE SIGNAL ;
    SHAPE ABUTMENT ;
    PORT
      LAYER M3 ;
      RECT 42.687 0.000 42.705 0.054 ;
    END
  END rw0_rd_out[108]
  PIN rw0_rd_out[109]
    DIRECTION OUTPUT ;
    USE SIGNAL ;
    SHAPE ABUTMENT ;
    PORT
      LAYER M3 ;
      RECT 42.867 0.000 42.885 0.054 ;
    END
  END rw0_rd_out[109]
  PIN rw0_rd_out[110]
    DIRECTION OUTPUT ;
    USE SIGNAL ;
    SHAPE ABUTMENT ;
    PORT
      LAYER M3 ;
      RECT 43.047 0.000 43.065 0.054 ;
    END
  END rw0_rd_out[110]
  PIN rw0_rd_out[111]
    DIRECTION OUTPUT ;
    USE SIGNAL ;
    SHAPE ABUTMENT ;
    PORT
      LAYER M3 ;
      RECT 43.227 0.000 43.245 0.054 ;
    END
  END rw0_rd_out[111]
  PIN rw0_rd_out[112]
    DIRECTION OUTPUT ;
    USE SIGNAL ;
    SHAPE ABUTMENT ;
    PORT
      LAYER M3 ;
      RECT 43.407 0.000 43.425 0.054 ;
    END
  END rw0_rd_out[112]
  PIN rw0_rd_out[113]
    DIRECTION OUTPUT ;
    USE SIGNAL ;
    SHAPE ABUTMENT ;
    PORT
      LAYER M3 ;
      RECT 43.587 0.000 43.605 0.054 ;
    END
  END rw0_rd_out[113]
  PIN rw0_rd_out[114]
    DIRECTION OUTPUT ;
    USE SIGNAL ;
    SHAPE ABUTMENT ;
    PORT
      LAYER M3 ;
      RECT 43.767 0.000 43.785 0.054 ;
    END
  END rw0_rd_out[114]
  PIN rw0_rd_out[115]
    DIRECTION OUTPUT ;
    USE SIGNAL ;
    SHAPE ABUTMENT ;
    PORT
      LAYER M3 ;
      RECT 43.947 0.000 43.965 0.054 ;
    END
  END rw0_rd_out[115]
  PIN rw0_rd_out[116]
    DIRECTION OUTPUT ;
    USE SIGNAL ;
    SHAPE ABUTMENT ;
    PORT
      LAYER M3 ;
      RECT 44.127 0.000 44.145 0.054 ;
    END
  END rw0_rd_out[116]
  PIN rw0_rd_out[117]
    DIRECTION OUTPUT ;
    USE SIGNAL ;
    SHAPE ABUTMENT ;
    PORT
      LAYER M3 ;
      RECT 44.307 0.000 44.325 0.054 ;
    END
  END rw0_rd_out[117]
  PIN rw0_rd_out[118]
    DIRECTION OUTPUT ;
    USE SIGNAL ;
    SHAPE ABUTMENT ;
    PORT
      LAYER M3 ;
      RECT 44.487 0.000 44.505 0.054 ;
    END
  END rw0_rd_out[118]
  PIN rw0_rd_out[119]
    DIRECTION OUTPUT ;
    USE SIGNAL ;
    SHAPE ABUTMENT ;
    PORT
      LAYER M3 ;
      RECT 44.667 0.000 44.685 0.054 ;
    END
  END rw0_rd_out[119]
  PIN rw0_rd_out[120]
    DIRECTION OUTPUT ;
    USE SIGNAL ;
    SHAPE ABUTMENT ;
    PORT
      LAYER M3 ;
      RECT 44.847 0.000 44.865 0.054 ;
    END
  END rw0_rd_out[120]
  PIN rw0_rd_out[121]
    DIRECTION OUTPUT ;
    USE SIGNAL ;
    SHAPE ABUTMENT ;
    PORT
      LAYER M3 ;
      RECT 45.027 0.000 45.045 0.054 ;
    END
  END rw0_rd_out[121]
  PIN rw0_rd_out[122]
    DIRECTION OUTPUT ;
    USE SIGNAL ;
    SHAPE ABUTMENT ;
    PORT
      LAYER M3 ;
      RECT 45.207 0.000 45.225 0.054 ;
    END
  END rw0_rd_out[122]
  PIN rw0_rd_out[123]
    DIRECTION OUTPUT ;
    USE SIGNAL ;
    SHAPE ABUTMENT ;
    PORT
      LAYER M3 ;
      RECT 45.387 0.000 45.405 0.054 ;
    END
  END rw0_rd_out[123]
  PIN rw0_rd_out[124]
    DIRECTION OUTPUT ;
    USE SIGNAL ;
    SHAPE ABUTMENT ;
    PORT
      LAYER M3 ;
      RECT 45.567 0.000 45.585 0.054 ;
    END
  END rw0_rd_out[124]
  PIN rw0_rd_out[125]
    DIRECTION OUTPUT ;
    USE SIGNAL ;
    SHAPE ABUTMENT ;
    PORT
      LAYER M3 ;
      RECT 45.747 0.000 45.765 0.054 ;
    END
  END rw0_rd_out[125]
  PIN rw0_rd_out[126]
    DIRECTION OUTPUT ;
    USE SIGNAL ;
    SHAPE ABUTMENT ;
    PORT
      LAYER M3 ;
      RECT 45.927 0.000 45.945 0.054 ;
    END
  END rw0_rd_out[126]
  PIN rw0_rd_out[127]
    DIRECTION OUTPUT ;
    USE SIGNAL ;
    SHAPE ABUTMENT ;
    PORT
      LAYER M3 ;
      RECT 46.107 0.000 46.125 0.054 ;
    END
  END rw0_rd_out[127]
  PIN rw0_rd_out[128]
    DIRECTION OUTPUT ;
    USE SIGNAL ;
    SHAPE ABUTMENT ;
    PORT
      LAYER M3 ;
      RECT 0.207 41.418 0.225 41.472 ;
    END
  END rw0_rd_out[128]
  PIN rw0_rd_out[129]
    DIRECTION OUTPUT ;
    USE SIGNAL ;
    SHAPE ABUTMENT ;
    PORT
      LAYER M3 ;
      RECT 0.567 41.418 0.585 41.472 ;
    END
  END rw0_rd_out[129]
  PIN rw0_rd_out[130]
    DIRECTION OUTPUT ;
    USE SIGNAL ;
    SHAPE ABUTMENT ;
    PORT
      LAYER M3 ;
      RECT 0.927 41.418 0.945 41.472 ;
    END
  END rw0_rd_out[130]
  PIN rw0_rd_out[131]
    DIRECTION OUTPUT ;
    USE SIGNAL ;
    SHAPE ABUTMENT ;
    PORT
      LAYER M3 ;
      RECT 1.287 41.418 1.305 41.472 ;
    END
  END rw0_rd_out[131]
  PIN rw0_rd_out[132]
    DIRECTION OUTPUT ;
    USE SIGNAL ;
    SHAPE ABUTMENT ;
    PORT
      LAYER M3 ;
      RECT 1.647 41.418 1.665 41.472 ;
    END
  END rw0_rd_out[132]
  PIN rw0_rd_out[133]
    DIRECTION OUTPUT ;
    USE SIGNAL ;
    SHAPE ABUTMENT ;
    PORT
      LAYER M3 ;
      RECT 2.007 41.418 2.025 41.472 ;
    END
  END rw0_rd_out[133]
  PIN rw0_rd_out[134]
    DIRECTION OUTPUT ;
    USE SIGNAL ;
    SHAPE ABUTMENT ;
    PORT
      LAYER M3 ;
      RECT 2.367 41.418 2.385 41.472 ;
    END
  END rw0_rd_out[134]
  PIN rw0_rd_out[135]
    DIRECTION OUTPUT ;
    USE SIGNAL ;
    SHAPE ABUTMENT ;
    PORT
      LAYER M3 ;
      RECT 2.727 41.418 2.745 41.472 ;
    END
  END rw0_rd_out[135]
  PIN rw0_rd_out[136]
    DIRECTION OUTPUT ;
    USE SIGNAL ;
    SHAPE ABUTMENT ;
    PORT
      LAYER M3 ;
      RECT 3.087 41.418 3.105 41.472 ;
    END
  END rw0_rd_out[136]
  PIN rw0_rd_out[137]
    DIRECTION OUTPUT ;
    USE SIGNAL ;
    SHAPE ABUTMENT ;
    PORT
      LAYER M3 ;
      RECT 3.447 41.418 3.465 41.472 ;
    END
  END rw0_rd_out[137]
  PIN rw0_rd_out[138]
    DIRECTION OUTPUT ;
    USE SIGNAL ;
    SHAPE ABUTMENT ;
    PORT
      LAYER M3 ;
      RECT 3.807 41.418 3.825 41.472 ;
    END
  END rw0_rd_out[138]
  PIN rw0_rd_out[139]
    DIRECTION OUTPUT ;
    USE SIGNAL ;
    SHAPE ABUTMENT ;
    PORT
      LAYER M3 ;
      RECT 4.167 41.418 4.185 41.472 ;
    END
  END rw0_rd_out[139]
  PIN rw0_rd_out[140]
    DIRECTION OUTPUT ;
    USE SIGNAL ;
    SHAPE ABUTMENT ;
    PORT
      LAYER M3 ;
      RECT 4.527 41.418 4.545 41.472 ;
    END
  END rw0_rd_out[140]
  PIN rw0_rd_out[141]
    DIRECTION OUTPUT ;
    USE SIGNAL ;
    SHAPE ABUTMENT ;
    PORT
      LAYER M3 ;
      RECT 4.887 41.418 4.905 41.472 ;
    END
  END rw0_rd_out[141]
  PIN rw0_rd_out[142]
    DIRECTION OUTPUT ;
    USE SIGNAL ;
    SHAPE ABUTMENT ;
    PORT
      LAYER M3 ;
      RECT 5.247 41.418 5.265 41.472 ;
    END
  END rw0_rd_out[142]
  PIN rw0_rd_out[143]
    DIRECTION OUTPUT ;
    USE SIGNAL ;
    SHAPE ABUTMENT ;
    PORT
      LAYER M3 ;
      RECT 5.607 41.418 5.625 41.472 ;
    END
  END rw0_rd_out[143]
  PIN rw0_rd_out[144]
    DIRECTION OUTPUT ;
    USE SIGNAL ;
    SHAPE ABUTMENT ;
    PORT
      LAYER M3 ;
      RECT 5.967 41.418 5.985 41.472 ;
    END
  END rw0_rd_out[144]
  PIN rw0_rd_out[145]
    DIRECTION OUTPUT ;
    USE SIGNAL ;
    SHAPE ABUTMENT ;
    PORT
      LAYER M3 ;
      RECT 6.327 41.418 6.345 41.472 ;
    END
  END rw0_rd_out[145]
  PIN rw0_rd_out[146]
    DIRECTION OUTPUT ;
    USE SIGNAL ;
    SHAPE ABUTMENT ;
    PORT
      LAYER M3 ;
      RECT 6.687 41.418 6.705 41.472 ;
    END
  END rw0_rd_out[146]
  PIN rw0_rd_out[147]
    DIRECTION OUTPUT ;
    USE SIGNAL ;
    SHAPE ABUTMENT ;
    PORT
      LAYER M3 ;
      RECT 7.047 41.418 7.065 41.472 ;
    END
  END rw0_rd_out[147]
  PIN rw0_rd_out[148]
    DIRECTION OUTPUT ;
    USE SIGNAL ;
    SHAPE ABUTMENT ;
    PORT
      LAYER M3 ;
      RECT 7.407 41.418 7.425 41.472 ;
    END
  END rw0_rd_out[148]
  PIN rw0_rd_out[149]
    DIRECTION OUTPUT ;
    USE SIGNAL ;
    SHAPE ABUTMENT ;
    PORT
      LAYER M3 ;
      RECT 7.767 41.418 7.785 41.472 ;
    END
  END rw0_rd_out[149]
  PIN rw0_rd_out[150]
    DIRECTION OUTPUT ;
    USE SIGNAL ;
    SHAPE ABUTMENT ;
    PORT
      LAYER M3 ;
      RECT 8.127 41.418 8.145 41.472 ;
    END
  END rw0_rd_out[150]
  PIN rw0_rd_out[151]
    DIRECTION OUTPUT ;
    USE SIGNAL ;
    SHAPE ABUTMENT ;
    PORT
      LAYER M3 ;
      RECT 8.487 41.418 8.505 41.472 ;
    END
  END rw0_rd_out[151]
  PIN rw0_rd_out[152]
    DIRECTION OUTPUT ;
    USE SIGNAL ;
    SHAPE ABUTMENT ;
    PORT
      LAYER M3 ;
      RECT 8.847 41.418 8.865 41.472 ;
    END
  END rw0_rd_out[152]
  PIN rw0_rd_out[153]
    DIRECTION OUTPUT ;
    USE SIGNAL ;
    SHAPE ABUTMENT ;
    PORT
      LAYER M3 ;
      RECT 9.207 41.418 9.225 41.472 ;
    END
  END rw0_rd_out[153]
  PIN rw0_rd_out[154]
    DIRECTION OUTPUT ;
    USE SIGNAL ;
    SHAPE ABUTMENT ;
    PORT
      LAYER M3 ;
      RECT 9.567 41.418 9.585 41.472 ;
    END
  END rw0_rd_out[154]
  PIN rw0_rd_out[155]
    DIRECTION OUTPUT ;
    USE SIGNAL ;
    SHAPE ABUTMENT ;
    PORT
      LAYER M3 ;
      RECT 9.927 41.418 9.945 41.472 ;
    END
  END rw0_rd_out[155]
  PIN rw0_rd_out[156]
    DIRECTION OUTPUT ;
    USE SIGNAL ;
    SHAPE ABUTMENT ;
    PORT
      LAYER M3 ;
      RECT 10.287 41.418 10.305 41.472 ;
    END
  END rw0_rd_out[156]
  PIN rw0_rd_out[157]
    DIRECTION OUTPUT ;
    USE SIGNAL ;
    SHAPE ABUTMENT ;
    PORT
      LAYER M3 ;
      RECT 10.647 41.418 10.665 41.472 ;
    END
  END rw0_rd_out[157]
  PIN rw0_rd_out[158]
    DIRECTION OUTPUT ;
    USE SIGNAL ;
    SHAPE ABUTMENT ;
    PORT
      LAYER M3 ;
      RECT 11.007 41.418 11.025 41.472 ;
    END
  END rw0_rd_out[158]
  PIN rw0_rd_out[159]
    DIRECTION OUTPUT ;
    USE SIGNAL ;
    SHAPE ABUTMENT ;
    PORT
      LAYER M3 ;
      RECT 11.367 41.418 11.385 41.472 ;
    END
  END rw0_rd_out[159]
  PIN rw0_rd_out[160]
    DIRECTION OUTPUT ;
    USE SIGNAL ;
    SHAPE ABUTMENT ;
    PORT
      LAYER M3 ;
      RECT 11.727 41.418 11.745 41.472 ;
    END
  END rw0_rd_out[160]
  PIN rw0_rd_out[161]
    DIRECTION OUTPUT ;
    USE SIGNAL ;
    SHAPE ABUTMENT ;
    PORT
      LAYER M3 ;
      RECT 12.087 41.418 12.105 41.472 ;
    END
  END rw0_rd_out[161]
  PIN rw0_rd_out[162]
    DIRECTION OUTPUT ;
    USE SIGNAL ;
    SHAPE ABUTMENT ;
    PORT
      LAYER M3 ;
      RECT 12.447 41.418 12.465 41.472 ;
    END
  END rw0_rd_out[162]
  PIN rw0_rd_out[163]
    DIRECTION OUTPUT ;
    USE SIGNAL ;
    SHAPE ABUTMENT ;
    PORT
      LAYER M3 ;
      RECT 12.807 41.418 12.825 41.472 ;
    END
  END rw0_rd_out[163]
  PIN rw0_rd_out[164]
    DIRECTION OUTPUT ;
    USE SIGNAL ;
    SHAPE ABUTMENT ;
    PORT
      LAYER M3 ;
      RECT 13.167 41.418 13.185 41.472 ;
    END
  END rw0_rd_out[164]
  PIN rw0_rd_out[165]
    DIRECTION OUTPUT ;
    USE SIGNAL ;
    SHAPE ABUTMENT ;
    PORT
      LAYER M3 ;
      RECT 13.527 41.418 13.545 41.472 ;
    END
  END rw0_rd_out[165]
  PIN rw0_rd_out[166]
    DIRECTION OUTPUT ;
    USE SIGNAL ;
    SHAPE ABUTMENT ;
    PORT
      LAYER M3 ;
      RECT 13.887 41.418 13.905 41.472 ;
    END
  END rw0_rd_out[166]
  PIN rw0_rd_out[167]
    DIRECTION OUTPUT ;
    USE SIGNAL ;
    SHAPE ABUTMENT ;
    PORT
      LAYER M3 ;
      RECT 14.247 41.418 14.265 41.472 ;
    END
  END rw0_rd_out[167]
  PIN rw0_rd_out[168]
    DIRECTION OUTPUT ;
    USE SIGNAL ;
    SHAPE ABUTMENT ;
    PORT
      LAYER M3 ;
      RECT 14.607 41.418 14.625 41.472 ;
    END
  END rw0_rd_out[168]
  PIN rw0_rd_out[169]
    DIRECTION OUTPUT ;
    USE SIGNAL ;
    SHAPE ABUTMENT ;
    PORT
      LAYER M3 ;
      RECT 14.967 41.418 14.985 41.472 ;
    END
  END rw0_rd_out[169]
  PIN rw0_rd_out[170]
    DIRECTION OUTPUT ;
    USE SIGNAL ;
    SHAPE ABUTMENT ;
    PORT
      LAYER M3 ;
      RECT 15.327 41.418 15.345 41.472 ;
    END
  END rw0_rd_out[170]
  PIN rw0_rd_out[171]
    DIRECTION OUTPUT ;
    USE SIGNAL ;
    SHAPE ABUTMENT ;
    PORT
      LAYER M3 ;
      RECT 15.687 41.418 15.705 41.472 ;
    END
  END rw0_rd_out[171]
  PIN rw0_rd_out[172]
    DIRECTION OUTPUT ;
    USE SIGNAL ;
    SHAPE ABUTMENT ;
    PORT
      LAYER M3 ;
      RECT 16.047 41.418 16.065 41.472 ;
    END
  END rw0_rd_out[172]
  PIN rw0_rd_out[173]
    DIRECTION OUTPUT ;
    USE SIGNAL ;
    SHAPE ABUTMENT ;
    PORT
      LAYER M3 ;
      RECT 16.407 41.418 16.425 41.472 ;
    END
  END rw0_rd_out[173]
  PIN rw0_rd_out[174]
    DIRECTION OUTPUT ;
    USE SIGNAL ;
    SHAPE ABUTMENT ;
    PORT
      LAYER M3 ;
      RECT 16.767 41.418 16.785 41.472 ;
    END
  END rw0_rd_out[174]
  PIN rw0_rd_out[175]
    DIRECTION OUTPUT ;
    USE SIGNAL ;
    SHAPE ABUTMENT ;
    PORT
      LAYER M3 ;
      RECT 17.127 41.418 17.145 41.472 ;
    END
  END rw0_rd_out[175]
  PIN rw0_rd_out[176]
    DIRECTION OUTPUT ;
    USE SIGNAL ;
    SHAPE ABUTMENT ;
    PORT
      LAYER M3 ;
      RECT 17.487 41.418 17.505 41.472 ;
    END
  END rw0_rd_out[176]
  PIN rw0_rd_out[177]
    DIRECTION OUTPUT ;
    USE SIGNAL ;
    SHAPE ABUTMENT ;
    PORT
      LAYER M3 ;
      RECT 17.847 41.418 17.865 41.472 ;
    END
  END rw0_rd_out[177]
  PIN rw0_rd_out[178]
    DIRECTION OUTPUT ;
    USE SIGNAL ;
    SHAPE ABUTMENT ;
    PORT
      LAYER M3 ;
      RECT 18.207 41.418 18.225 41.472 ;
    END
  END rw0_rd_out[178]
  PIN rw0_rd_out[179]
    DIRECTION OUTPUT ;
    USE SIGNAL ;
    SHAPE ABUTMENT ;
    PORT
      LAYER M3 ;
      RECT 18.567 41.418 18.585 41.472 ;
    END
  END rw0_rd_out[179]
  PIN rw0_rd_out[180]
    DIRECTION OUTPUT ;
    USE SIGNAL ;
    SHAPE ABUTMENT ;
    PORT
      LAYER M3 ;
      RECT 18.927 41.418 18.945 41.472 ;
    END
  END rw0_rd_out[180]
  PIN rw0_rd_out[181]
    DIRECTION OUTPUT ;
    USE SIGNAL ;
    SHAPE ABUTMENT ;
    PORT
      LAYER M3 ;
      RECT 19.287 41.418 19.305 41.472 ;
    END
  END rw0_rd_out[181]
  PIN rw0_rd_out[182]
    DIRECTION OUTPUT ;
    USE SIGNAL ;
    SHAPE ABUTMENT ;
    PORT
      LAYER M3 ;
      RECT 19.647 41.418 19.665 41.472 ;
    END
  END rw0_rd_out[182]
  PIN rw0_rd_out[183]
    DIRECTION OUTPUT ;
    USE SIGNAL ;
    SHAPE ABUTMENT ;
    PORT
      LAYER M3 ;
      RECT 20.007 41.418 20.025 41.472 ;
    END
  END rw0_rd_out[183]
  PIN rw0_rd_out[184]
    DIRECTION OUTPUT ;
    USE SIGNAL ;
    SHAPE ABUTMENT ;
    PORT
      LAYER M3 ;
      RECT 20.367 41.418 20.385 41.472 ;
    END
  END rw0_rd_out[184]
  PIN rw0_rd_out[185]
    DIRECTION OUTPUT ;
    USE SIGNAL ;
    SHAPE ABUTMENT ;
    PORT
      LAYER M3 ;
      RECT 20.727 41.418 20.745 41.472 ;
    END
  END rw0_rd_out[185]
  PIN rw0_rd_out[186]
    DIRECTION OUTPUT ;
    USE SIGNAL ;
    SHAPE ABUTMENT ;
    PORT
      LAYER M3 ;
      RECT 21.087 41.418 21.105 41.472 ;
    END
  END rw0_rd_out[186]
  PIN rw0_rd_out[187]
    DIRECTION OUTPUT ;
    USE SIGNAL ;
    SHAPE ABUTMENT ;
    PORT
      LAYER M3 ;
      RECT 21.447 41.418 21.465 41.472 ;
    END
  END rw0_rd_out[187]
  PIN rw0_rd_out[188]
    DIRECTION OUTPUT ;
    USE SIGNAL ;
    SHAPE ABUTMENT ;
    PORT
      LAYER M3 ;
      RECT 21.807 41.418 21.825 41.472 ;
    END
  END rw0_rd_out[188]
  PIN rw0_rd_out[189]
    DIRECTION OUTPUT ;
    USE SIGNAL ;
    SHAPE ABUTMENT ;
    PORT
      LAYER M3 ;
      RECT 22.167 41.418 22.185 41.472 ;
    END
  END rw0_rd_out[189]
  PIN rw0_rd_out[190]
    DIRECTION OUTPUT ;
    USE SIGNAL ;
    SHAPE ABUTMENT ;
    PORT
      LAYER M3 ;
      RECT 22.527 41.418 22.545 41.472 ;
    END
  END rw0_rd_out[190]
  PIN rw0_rd_out[191]
    DIRECTION OUTPUT ;
    USE SIGNAL ;
    SHAPE ABUTMENT ;
    PORT
      LAYER M3 ;
      RECT 22.887 41.418 22.905 41.472 ;
    END
  END rw0_rd_out[191]
  PIN rw0_rd_out[192]
    DIRECTION OUTPUT ;
    USE SIGNAL ;
    SHAPE ABUTMENT ;
    PORT
      LAYER M3 ;
      RECT 23.247 41.418 23.265 41.472 ;
    END
  END rw0_rd_out[192]
  PIN rw0_rd_out[193]
    DIRECTION OUTPUT ;
    USE SIGNAL ;
    SHAPE ABUTMENT ;
    PORT
      LAYER M3 ;
      RECT 23.607 41.418 23.625 41.472 ;
    END
  END rw0_rd_out[193]
  PIN rw0_rd_out[194]
    DIRECTION OUTPUT ;
    USE SIGNAL ;
    SHAPE ABUTMENT ;
    PORT
      LAYER M3 ;
      RECT 23.967 41.418 23.985 41.472 ;
    END
  END rw0_rd_out[194]
  PIN rw0_rd_out[195]
    DIRECTION OUTPUT ;
    USE SIGNAL ;
    SHAPE ABUTMENT ;
    PORT
      LAYER M3 ;
      RECT 24.327 41.418 24.345 41.472 ;
    END
  END rw0_rd_out[195]
  PIN rw0_rd_out[196]
    DIRECTION OUTPUT ;
    USE SIGNAL ;
    SHAPE ABUTMENT ;
    PORT
      LAYER M3 ;
      RECT 24.687 41.418 24.705 41.472 ;
    END
  END rw0_rd_out[196]
  PIN rw0_rd_out[197]
    DIRECTION OUTPUT ;
    USE SIGNAL ;
    SHAPE ABUTMENT ;
    PORT
      LAYER M3 ;
      RECT 25.047 41.418 25.065 41.472 ;
    END
  END rw0_rd_out[197]
  PIN rw0_rd_out[198]
    DIRECTION OUTPUT ;
    USE SIGNAL ;
    SHAPE ABUTMENT ;
    PORT
      LAYER M3 ;
      RECT 25.407 41.418 25.425 41.472 ;
    END
  END rw0_rd_out[198]
  PIN rw0_rd_out[199]
    DIRECTION OUTPUT ;
    USE SIGNAL ;
    SHAPE ABUTMENT ;
    PORT
      LAYER M3 ;
      RECT 25.767 41.418 25.785 41.472 ;
    END
  END rw0_rd_out[199]
  PIN rw0_rd_out[200]
    DIRECTION OUTPUT ;
    USE SIGNAL ;
    SHAPE ABUTMENT ;
    PORT
      LAYER M3 ;
      RECT 26.127 41.418 26.145 41.472 ;
    END
  END rw0_rd_out[200]
  PIN rw0_rd_out[201]
    DIRECTION OUTPUT ;
    USE SIGNAL ;
    SHAPE ABUTMENT ;
    PORT
      LAYER M3 ;
      RECT 26.487 41.418 26.505 41.472 ;
    END
  END rw0_rd_out[201]
  PIN rw0_rd_out[202]
    DIRECTION OUTPUT ;
    USE SIGNAL ;
    SHAPE ABUTMENT ;
    PORT
      LAYER M3 ;
      RECT 26.847 41.418 26.865 41.472 ;
    END
  END rw0_rd_out[202]
  PIN rw0_rd_out[203]
    DIRECTION OUTPUT ;
    USE SIGNAL ;
    SHAPE ABUTMENT ;
    PORT
      LAYER M3 ;
      RECT 27.207 41.418 27.225 41.472 ;
    END
  END rw0_rd_out[203]
  PIN rw0_rd_out[204]
    DIRECTION OUTPUT ;
    USE SIGNAL ;
    SHAPE ABUTMENT ;
    PORT
      LAYER M3 ;
      RECT 27.567 41.418 27.585 41.472 ;
    END
  END rw0_rd_out[204]
  PIN rw0_rd_out[205]
    DIRECTION OUTPUT ;
    USE SIGNAL ;
    SHAPE ABUTMENT ;
    PORT
      LAYER M3 ;
      RECT 27.927 41.418 27.945 41.472 ;
    END
  END rw0_rd_out[205]
  PIN rw0_rd_out[206]
    DIRECTION OUTPUT ;
    USE SIGNAL ;
    SHAPE ABUTMENT ;
    PORT
      LAYER M3 ;
      RECT 28.287 41.418 28.305 41.472 ;
    END
  END rw0_rd_out[206]
  PIN rw0_rd_out[207]
    DIRECTION OUTPUT ;
    USE SIGNAL ;
    SHAPE ABUTMENT ;
    PORT
      LAYER M3 ;
      RECT 28.647 41.418 28.665 41.472 ;
    END
  END rw0_rd_out[207]
  PIN rw0_rd_out[208]
    DIRECTION OUTPUT ;
    USE SIGNAL ;
    SHAPE ABUTMENT ;
    PORT
      LAYER M3 ;
      RECT 29.007 41.418 29.025 41.472 ;
    END
  END rw0_rd_out[208]
  PIN rw0_rd_out[209]
    DIRECTION OUTPUT ;
    USE SIGNAL ;
    SHAPE ABUTMENT ;
    PORT
      LAYER M3 ;
      RECT 29.367 41.418 29.385 41.472 ;
    END
  END rw0_rd_out[209]
  PIN rw0_rd_out[210]
    DIRECTION OUTPUT ;
    USE SIGNAL ;
    SHAPE ABUTMENT ;
    PORT
      LAYER M3 ;
      RECT 29.727 41.418 29.745 41.472 ;
    END
  END rw0_rd_out[210]
  PIN rw0_rd_out[211]
    DIRECTION OUTPUT ;
    USE SIGNAL ;
    SHAPE ABUTMENT ;
    PORT
      LAYER M3 ;
      RECT 30.087 41.418 30.105 41.472 ;
    END
  END rw0_rd_out[211]
  PIN rw0_rd_out[212]
    DIRECTION OUTPUT ;
    USE SIGNAL ;
    SHAPE ABUTMENT ;
    PORT
      LAYER M3 ;
      RECT 30.447 41.418 30.465 41.472 ;
    END
  END rw0_rd_out[212]
  PIN rw0_rd_out[213]
    DIRECTION OUTPUT ;
    USE SIGNAL ;
    SHAPE ABUTMENT ;
    PORT
      LAYER M3 ;
      RECT 30.807 41.418 30.825 41.472 ;
    END
  END rw0_rd_out[213]
  PIN rw0_rd_out[214]
    DIRECTION OUTPUT ;
    USE SIGNAL ;
    SHAPE ABUTMENT ;
    PORT
      LAYER M3 ;
      RECT 31.167 41.418 31.185 41.472 ;
    END
  END rw0_rd_out[214]
  PIN rw0_rd_out[215]
    DIRECTION OUTPUT ;
    USE SIGNAL ;
    SHAPE ABUTMENT ;
    PORT
      LAYER M3 ;
      RECT 31.527 41.418 31.545 41.472 ;
    END
  END rw0_rd_out[215]
  PIN rw0_rd_out[216]
    DIRECTION OUTPUT ;
    USE SIGNAL ;
    SHAPE ABUTMENT ;
    PORT
      LAYER M3 ;
      RECT 31.887 41.418 31.905 41.472 ;
    END
  END rw0_rd_out[216]
  PIN rw0_rd_out[217]
    DIRECTION OUTPUT ;
    USE SIGNAL ;
    SHAPE ABUTMENT ;
    PORT
      LAYER M3 ;
      RECT 32.247 41.418 32.265 41.472 ;
    END
  END rw0_rd_out[217]
  PIN rw0_rd_out[218]
    DIRECTION OUTPUT ;
    USE SIGNAL ;
    SHAPE ABUTMENT ;
    PORT
      LAYER M3 ;
      RECT 32.607 41.418 32.625 41.472 ;
    END
  END rw0_rd_out[218]
  PIN rw0_rd_out[219]
    DIRECTION OUTPUT ;
    USE SIGNAL ;
    SHAPE ABUTMENT ;
    PORT
      LAYER M3 ;
      RECT 32.967 41.418 32.985 41.472 ;
    END
  END rw0_rd_out[219]
  PIN rw0_rd_out[220]
    DIRECTION OUTPUT ;
    USE SIGNAL ;
    SHAPE ABUTMENT ;
    PORT
      LAYER M3 ;
      RECT 33.327 41.418 33.345 41.472 ;
    END
  END rw0_rd_out[220]
  PIN rw0_rd_out[221]
    DIRECTION OUTPUT ;
    USE SIGNAL ;
    SHAPE ABUTMENT ;
    PORT
      LAYER M3 ;
      RECT 33.687 41.418 33.705 41.472 ;
    END
  END rw0_rd_out[221]
  PIN rw0_rd_out[222]
    DIRECTION OUTPUT ;
    USE SIGNAL ;
    SHAPE ABUTMENT ;
    PORT
      LAYER M3 ;
      RECT 34.047 41.418 34.065 41.472 ;
    END
  END rw0_rd_out[222]
  PIN rw0_rd_out[223]
    DIRECTION OUTPUT ;
    USE SIGNAL ;
    SHAPE ABUTMENT ;
    PORT
      LAYER M3 ;
      RECT 34.407 41.418 34.425 41.472 ;
    END
  END rw0_rd_out[223]
  PIN rw0_rd_out[224]
    DIRECTION OUTPUT ;
    USE SIGNAL ;
    SHAPE ABUTMENT ;
    PORT
      LAYER M3 ;
      RECT 34.767 41.418 34.785 41.472 ;
    END
  END rw0_rd_out[224]
  PIN rw0_rd_out[225]
    DIRECTION OUTPUT ;
    USE SIGNAL ;
    SHAPE ABUTMENT ;
    PORT
      LAYER M3 ;
      RECT 35.127 41.418 35.145 41.472 ;
    END
  END rw0_rd_out[225]
  PIN rw0_rd_out[226]
    DIRECTION OUTPUT ;
    USE SIGNAL ;
    SHAPE ABUTMENT ;
    PORT
      LAYER M3 ;
      RECT 35.487 41.418 35.505 41.472 ;
    END
  END rw0_rd_out[226]
  PIN rw0_rd_out[227]
    DIRECTION OUTPUT ;
    USE SIGNAL ;
    SHAPE ABUTMENT ;
    PORT
      LAYER M3 ;
      RECT 35.847 41.418 35.865 41.472 ;
    END
  END rw0_rd_out[227]
  PIN rw0_rd_out[228]
    DIRECTION OUTPUT ;
    USE SIGNAL ;
    SHAPE ABUTMENT ;
    PORT
      LAYER M3 ;
      RECT 36.207 41.418 36.225 41.472 ;
    END
  END rw0_rd_out[228]
  PIN rw0_rd_out[229]
    DIRECTION OUTPUT ;
    USE SIGNAL ;
    SHAPE ABUTMENT ;
    PORT
      LAYER M3 ;
      RECT 36.567 41.418 36.585 41.472 ;
    END
  END rw0_rd_out[229]
  PIN rw0_rd_out[230]
    DIRECTION OUTPUT ;
    USE SIGNAL ;
    SHAPE ABUTMENT ;
    PORT
      LAYER M3 ;
      RECT 36.927 41.418 36.945 41.472 ;
    END
  END rw0_rd_out[230]
  PIN rw0_rd_out[231]
    DIRECTION OUTPUT ;
    USE SIGNAL ;
    SHAPE ABUTMENT ;
    PORT
      LAYER M3 ;
      RECT 37.287 41.418 37.305 41.472 ;
    END
  END rw0_rd_out[231]
  PIN rw0_rd_out[232]
    DIRECTION OUTPUT ;
    USE SIGNAL ;
    SHAPE ABUTMENT ;
    PORT
      LAYER M3 ;
      RECT 37.647 41.418 37.665 41.472 ;
    END
  END rw0_rd_out[232]
  PIN rw0_rd_out[233]
    DIRECTION OUTPUT ;
    USE SIGNAL ;
    SHAPE ABUTMENT ;
    PORT
      LAYER M3 ;
      RECT 38.007 41.418 38.025 41.472 ;
    END
  END rw0_rd_out[233]
  PIN rw0_rd_out[234]
    DIRECTION OUTPUT ;
    USE SIGNAL ;
    SHAPE ABUTMENT ;
    PORT
      LAYER M3 ;
      RECT 38.367 41.418 38.385 41.472 ;
    END
  END rw0_rd_out[234]
  PIN rw0_rd_out[235]
    DIRECTION OUTPUT ;
    USE SIGNAL ;
    SHAPE ABUTMENT ;
    PORT
      LAYER M3 ;
      RECT 38.727 41.418 38.745 41.472 ;
    END
  END rw0_rd_out[235]
  PIN rw0_rd_out[236]
    DIRECTION OUTPUT ;
    USE SIGNAL ;
    SHAPE ABUTMENT ;
    PORT
      LAYER M3 ;
      RECT 39.087 41.418 39.105 41.472 ;
    END
  END rw0_rd_out[236]
  PIN rw0_rd_out[237]
    DIRECTION OUTPUT ;
    USE SIGNAL ;
    SHAPE ABUTMENT ;
    PORT
      LAYER M3 ;
      RECT 39.447 41.418 39.465 41.472 ;
    END
  END rw0_rd_out[237]
  PIN rw0_rd_out[238]
    DIRECTION OUTPUT ;
    USE SIGNAL ;
    SHAPE ABUTMENT ;
    PORT
      LAYER M3 ;
      RECT 39.807 41.418 39.825 41.472 ;
    END
  END rw0_rd_out[238]
  PIN rw0_rd_out[239]
    DIRECTION OUTPUT ;
    USE SIGNAL ;
    SHAPE ABUTMENT ;
    PORT
      LAYER M3 ;
      RECT 40.167 41.418 40.185 41.472 ;
    END
  END rw0_rd_out[239]
  PIN rw0_rd_out[240]
    DIRECTION OUTPUT ;
    USE SIGNAL ;
    SHAPE ABUTMENT ;
    PORT
      LAYER M3 ;
      RECT 40.527 41.418 40.545 41.472 ;
    END
  END rw0_rd_out[240]
  PIN rw0_rd_out[241]
    DIRECTION OUTPUT ;
    USE SIGNAL ;
    SHAPE ABUTMENT ;
    PORT
      LAYER M3 ;
      RECT 40.887 41.418 40.905 41.472 ;
    END
  END rw0_rd_out[241]
  PIN rw0_rd_out[242]
    DIRECTION OUTPUT ;
    USE SIGNAL ;
    SHAPE ABUTMENT ;
    PORT
      LAYER M3 ;
      RECT 41.247 41.418 41.265 41.472 ;
    END
  END rw0_rd_out[242]
  PIN rw0_rd_out[243]
    DIRECTION OUTPUT ;
    USE SIGNAL ;
    SHAPE ABUTMENT ;
    PORT
      LAYER M3 ;
      RECT 41.607 41.418 41.625 41.472 ;
    END
  END rw0_rd_out[243]
  PIN rw0_rd_out[244]
    DIRECTION OUTPUT ;
    USE SIGNAL ;
    SHAPE ABUTMENT ;
    PORT
      LAYER M3 ;
      RECT 41.967 41.418 41.985 41.472 ;
    END
  END rw0_rd_out[244]
  PIN rw0_rd_out[245]
    DIRECTION OUTPUT ;
    USE SIGNAL ;
    SHAPE ABUTMENT ;
    PORT
      LAYER M3 ;
      RECT 42.327 41.418 42.345 41.472 ;
    END
  END rw0_rd_out[245]
  PIN rw0_rd_out[246]
    DIRECTION OUTPUT ;
    USE SIGNAL ;
    SHAPE ABUTMENT ;
    PORT
      LAYER M3 ;
      RECT 42.687 41.418 42.705 41.472 ;
    END
  END rw0_rd_out[246]
  PIN rw0_rd_out[247]
    DIRECTION OUTPUT ;
    USE SIGNAL ;
    SHAPE ABUTMENT ;
    PORT
      LAYER M3 ;
      RECT 43.047 41.418 43.065 41.472 ;
    END
  END rw0_rd_out[247]
  PIN rw0_rd_out[248]
    DIRECTION OUTPUT ;
    USE SIGNAL ;
    SHAPE ABUTMENT ;
    PORT
      LAYER M3 ;
      RECT 43.407 41.418 43.425 41.472 ;
    END
  END rw0_rd_out[248]
  PIN rw0_rd_out[249]
    DIRECTION OUTPUT ;
    USE SIGNAL ;
    SHAPE ABUTMENT ;
    PORT
      LAYER M3 ;
      RECT 43.767 41.418 43.785 41.472 ;
    END
  END rw0_rd_out[249]
  PIN rw0_rd_out[250]
    DIRECTION OUTPUT ;
    USE SIGNAL ;
    SHAPE ABUTMENT ;
    PORT
      LAYER M3 ;
      RECT 44.127 41.418 44.145 41.472 ;
    END
  END rw0_rd_out[250]
  PIN rw0_rd_out[251]
    DIRECTION OUTPUT ;
    USE SIGNAL ;
    SHAPE ABUTMENT ;
    PORT
      LAYER M3 ;
      RECT 44.487 41.418 44.505 41.472 ;
    END
  END rw0_rd_out[251]
  PIN rw0_rd_out[252]
    DIRECTION OUTPUT ;
    USE SIGNAL ;
    SHAPE ABUTMENT ;
    PORT
      LAYER M3 ;
      RECT 44.847 41.418 44.865 41.472 ;
    END
  END rw0_rd_out[252]
  PIN rw0_rd_out[253]
    DIRECTION OUTPUT ;
    USE SIGNAL ;
    SHAPE ABUTMENT ;
    PORT
      LAYER M3 ;
      RECT 45.207 41.418 45.225 41.472 ;
    END
  END rw0_rd_out[253]
  PIN rw0_rd_out[254]
    DIRECTION OUTPUT ;
    USE SIGNAL ;
    SHAPE ABUTMENT ;
    PORT
      LAYER M3 ;
      RECT 45.567 41.418 45.585 41.472 ;
    END
  END rw0_rd_out[254]
  PIN rw0_rd_out[255]
    DIRECTION OUTPUT ;
    USE SIGNAL ;
    SHAPE ABUTMENT ;
    PORT
      LAYER M3 ;
      RECT 45.927 41.418 45.945 41.472 ;
    END
  END rw0_rd_out[255]
  PIN rw0_addr_in[0]
    DIRECTION INPUT ;
    USE SIGNAL ;
    SHAPE ABUTMENT ;
    PORT
      LAYER M4 ;
      RECT 0.000 37.140 0.072 37.164 ;
    END
  END rw0_addr_in[0]
  PIN rw0_addr_in[1]
    DIRECTION INPUT ;
    USE SIGNAL ;
    SHAPE ABUTMENT ;
    PORT
      LAYER M4 ;
      RECT 0.000 37.716 0.072 37.740 ;
    END
  END rw0_addr_in[1]
  PIN rw0_addr_in[2]
    DIRECTION INPUT ;
    USE SIGNAL ;
    SHAPE ABUTMENT ;
    PORT
      LAYER M4 ;
      RECT 0.000 38.292 0.072 38.316 ;
    END
  END rw0_addr_in[2]
  PIN rw0_addr_in[3]
    DIRECTION INPUT ;
    USE SIGNAL ;
    SHAPE ABUTMENT ;
    PORT
      LAYER M4 ;
      RECT 0.000 38.868 0.072 38.892 ;
    END
  END rw0_addr_in[3]
  PIN rw0_addr_in[4]
    DIRECTION INPUT ;
    USE SIGNAL ;
    SHAPE ABUTMENT ;
    PORT
      LAYER M4 ;
      RECT 49.695 37.140 49.767 37.164 ;
    END
  END rw0_addr_in[4]
  PIN rw0_addr_in[5]
    DIRECTION INPUT ;
    USE SIGNAL ;
    SHAPE ABUTMENT ;
    PORT
      LAYER M4 ;
      RECT 49.695 37.716 49.767 37.740 ;
    END
  END rw0_addr_in[5]
  PIN rw0_addr_in[6]
    DIRECTION INPUT ;
    USE SIGNAL ;
    SHAPE ABUTMENT ;
    PORT
      LAYER M4 ;
      RECT 49.695 38.292 49.767 38.316 ;
    END
  END rw0_addr_in[6]
  PIN rw0_addr_in[7]
    DIRECTION INPUT ;
    USE SIGNAL ;
    SHAPE ABUTMENT ;
    PORT
      LAYER M4 ;
      RECT 49.695 38.868 49.767 38.892 ;
    END
  END rw0_addr_in[7]
  PIN rw0_we_in
    DIRECTION INPUT ;
    USE SIGNAL ;
    SHAPE ABUTMENT ;
    PORT
      LAYER M3 ;
      RECT 46.287 41.418 46.305 41.472 ;
    END
  END rw0_we_in
  PIN rw0_ce_in
    DIRECTION INPUT ;
    USE SIGNAL ;
    SHAPE ABUTMENT ;
    PORT
      LAYER M3 ;
      RECT 46.647 41.418 46.665 41.472 ;
    END
  END rw0_ce_in
  PIN rw0_clk
    DIRECTION INPUT ;
    USE SIGNAL ;
    SHAPE ABUTMENT ;
    PORT
      LAYER M3 ;
      RECT 47.007 41.418 47.025 41.472 ;
    END
  END rw0_clk
  PIN VSS
    DIRECTION INOUT ;
    USE GROUND ;
    PORT
      LAYER M4 ;
      RECT 0.216 0.240 49.551 0.336 ;
      RECT 0.216 1.008 49.551 1.104 ;
      RECT 0.216 1.776 49.551 1.872 ;
      RECT 0.216 2.544 49.551 2.640 ;
      RECT 0.216 3.312 49.551 3.408 ;
      RECT 0.216 4.080 49.551 4.176 ;
      RECT 0.216 4.848 49.551 4.944 ;
      RECT 0.216 5.616 49.551 5.712 ;
      RECT 0.216 6.384 49.551 6.480 ;
      RECT 0.216 7.152 49.551 7.248 ;
      RECT 0.216 7.920 49.551 8.016 ;
      RECT 0.216 8.688 49.551 8.784 ;
      RECT 0.216 9.456 49.551 9.552 ;
      RECT 0.216 10.224 49.551 10.320 ;
      RECT 0.216 10.992 49.551 11.088 ;
      RECT 0.216 11.760 49.551 11.856 ;
      RECT 0.216 12.528 49.551 12.624 ;
      RECT 0.216 13.296 49.551 13.392 ;
      RECT 0.216 14.064 49.551 14.160 ;
      RECT 0.216 14.832 49.551 14.928 ;
      RECT 0.216 15.600 49.551 15.696 ;
      RECT 0.216 16.368 49.551 16.464 ;
      RECT 0.216 17.136 49.551 17.232 ;
      RECT 0.216 17.904 49.551 18.000 ;
      RECT 0.216 18.672 49.551 18.768 ;
      RECT 0.216 19.440 49.551 19.536 ;
      RECT 0.216 20.208 49.551 20.304 ;
      RECT 0.216 20.976 49.551 21.072 ;
      RECT 0.216 21.744 49.551 21.840 ;
      RECT 0.216 22.512 49.551 22.608 ;
      RECT 0.216 23.280 49.551 23.376 ;
      RECT 0.216 24.048 49.551 24.144 ;
      RECT 0.216 24.816 49.551 24.912 ;
      RECT 0.216 25.584 49.551 25.680 ;
      RECT 0.216 26.352 49.551 26.448 ;
      RECT 0.216 27.120 49.551 27.216 ;
      RECT 0.216 27.888 49.551 27.984 ;
      RECT 0.216 28.656 49.551 28.752 ;
      RECT 0.216 29.424 49.551 29.520 ;
      RECT 0.216 30.192 49.551 30.288 ;
      RECT 0.216 30.960 49.551 31.056 ;
      RECT 0.216 31.728 49.551 31.824 ;
      RECT 0.216 32.496 49.551 32.592 ;
      RECT 0.216 33.264 49.551 33.360 ;
      RECT 0.216 34.032 49.551 34.128 ;
      RECT 0.216 34.800 49.551 34.896 ;
      RECT 0.216 35.568 49.551 35.664 ;
      RECT 0.216 36.336 49.551 36.432 ;
      RECT 0.216 37.104 49.551 37.200 ;
      RECT 0.216 37.872 49.551 37.968 ;
      RECT 0.216 38.640 49.551 38.736 ;
      RECT 0.216 39.408 49.551 39.504 ;
      RECT 0.216 40.176 49.551 40.272 ;
      RECT 0.216 40.944 49.551 41.040 ;
    END
  END VSS
  PIN VDD
    DIRECTION INOUT ;
    USE POWER ;
    PORT
      LAYER M4 ;
      RECT 0.216 0.240 49.551 0.336 ;
      RECT 0.216 1.008 49.551 1.104 ;
      RECT 0.216 1.776 49.551 1.872 ;
      RECT 0.216 2.544 49.551 2.640 ;
      RECT 0.216 3.312 49.551 3.408 ;
      RECT 0.216 4.080 49.551 4.176 ;
      RECT 0.216 4.848 49.551 4.944 ;
      RECT 0.216 5.616 49.551 5.712 ;
      RECT 0.216 6.384 49.551 6.480 ;
      RECT 0.216 7.152 49.551 7.248 ;
      RECT 0.216 7.920 49.551 8.016 ;
      RECT 0.216 8.688 49.551 8.784 ;
      RECT 0.216 9.456 49.551 9.552 ;
      RECT 0.216 10.224 49.551 10.320 ;
      RECT 0.216 10.992 49.551 11.088 ;
      RECT 0.216 11.760 49.551 11.856 ;
      RECT 0.216 12.528 49.551 12.624 ;
      RECT 0.216 13.296 49.551 13.392 ;
      RECT 0.216 14.064 49.551 14.160 ;
      RECT 0.216 14.832 49.551 14.928 ;
      RECT 0.216 15.600 49.551 15.696 ;
      RECT 0.216 16.368 49.551 16.464 ;
      RECT 0.216 17.136 49.551 17.232 ;
      RECT 0.216 17.904 49.551 18.000 ;
      RECT 0.216 18.672 49.551 18.768 ;
      RECT 0.216 19.440 49.551 19.536 ;
      RECT 0.216 20.208 49.551 20.304 ;
      RECT 0.216 20.976 49.551 21.072 ;
      RECT 0.216 21.744 49.551 21.840 ;
      RECT 0.216 22.512 49.551 22.608 ;
      RECT 0.216 23.280 49.551 23.376 ;
      RECT 0.216 24.048 49.551 24.144 ;
      RECT 0.216 24.816 49.551 24.912 ;
      RECT 0.216 25.584 49.551 25.680 ;
      RECT 0.216 26.352 49.551 26.448 ;
      RECT 0.216 27.120 49.551 27.216 ;
      RECT 0.216 27.888 49.551 27.984 ;
      RECT 0.216 28.656 49.551 28.752 ;
      RECT 0.216 29.424 49.551 29.520 ;
      RECT 0.216 30.192 49.551 30.288 ;
      RECT 0.216 30.960 49.551 31.056 ;
      RECT 0.216 31.728 49.551 31.824 ;
      RECT 0.216 32.496 49.551 32.592 ;
      RECT 0.216 33.264 49.551 33.360 ;
      RECT 0.216 34.032 49.551 34.128 ;
      RECT 0.216 34.800 49.551 34.896 ;
      RECT 0.216 35.568 49.551 35.664 ;
      RECT 0.216 36.336 49.551 36.432 ;
      RECT 0.216 37.104 49.551 37.200 ;
      RECT 0.216 37.872 49.551 37.968 ;
      RECT 0.216 38.640 49.551 38.736 ;
      RECT 0.216 39.408 49.551 39.504 ;
      RECT 0.216 40.176 49.551 40.272 ;
      RECT 0.216 40.944 49.551 41.040 ;
    END
  END VDD
  OBS
    LAYER M1 ;
    RECT 0 0 49.767 41.472 ;
    LAYER M2 ;
    RECT 0 0 49.767 41.472 ;
    LAYER M3 ;
    RECT 0 0 49.767 41.472 ;
    LAYER M4 ;
    RECT 0 0 49.767 41.472 ;
  END
END fakeram7_256x256

END LIBRARY
